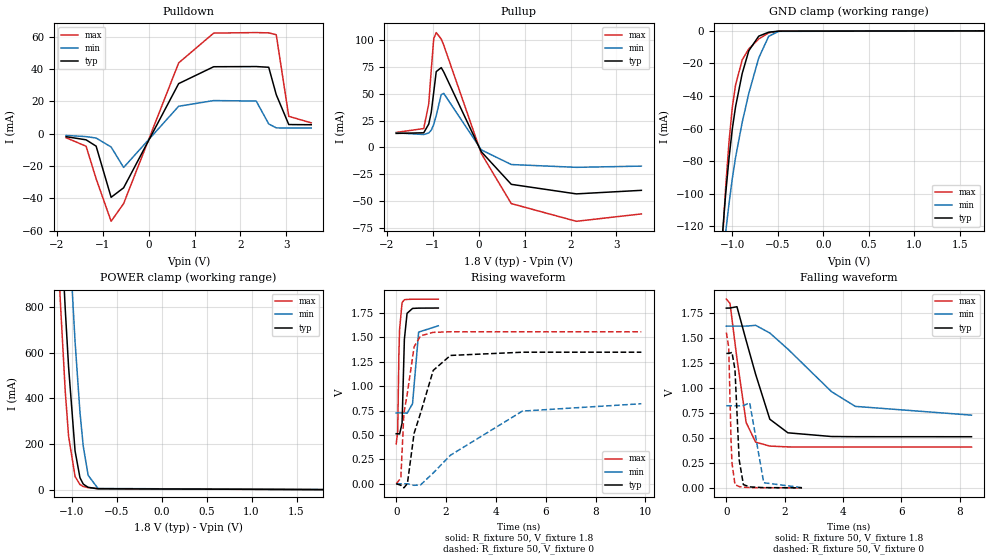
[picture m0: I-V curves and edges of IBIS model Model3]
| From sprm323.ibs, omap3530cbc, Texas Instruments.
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| Model based on original model for BQ0232CS_7LM
|   Sub model BQ0232CS_7LM_PU_ON_1P8
[model]   Model3
|[Input Load]   PU
|[Output Drive]
|Voltage   1.8V
|Mode   I/O
Model_type   I/O
Polarity   Non-Inverting
Enable   Active-Low
Vinl =  0.63
Vinh =  1.17
Cref =  15.0000pF
Rref =  100.0000M
Vref =  0V
Vmeas =  0.9
C_comp   0.8836195p   0.7578727p   1.042532p
[Model Spec]
Vinl   0.63   0.567   0.6615
Vinh   1.17   1.053   1.2285
[Temperature Range]   25   125   -40
[Voltage Range]   1.8   1.62   1.89
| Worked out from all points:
|   slope of the pulldown table from 0 to 0.27 V, typ, clamps not added: 18.2 ohm
|   slope of the pullup table from 0 to 0.27 V, typ, clamps not added: 15.1 ohm
|   GND clamp passes 1 mA (typ) near -0.61 V on its own axis
|   POWER clamp passes 1 mA (typ) near -0.57 V on its own axis
|   rising waveform, R_fixture 50, V_fixture 1.8: 20-80 % time 81.8ps typ, 143ps min, 65.1ps max; typ from 0.513 V to 1.8 V
|   rising waveform, R_fixture 50, V_fixture 0: 20-80 % time 778ps typ, 2.51ns min, 382ps max; typ from 0.001 V to 1.35 V
|   falling waveform, R_fixture 50, V_fixture 1.8: 20-80 % time 759ps typ, 1.98ns min, 424ps max; typ from 1.8 V to 0.513 V
|   falling waveform, R_fixture 50, V_fixture 0: 20-80 % time 127ps typ, 250ps min, 81.8ps max; typ from 1.35 V to 0.002 V
[POWER_clamp]
-1.8V     7.03A      7.477A     6.772A
-1.182V   1.672A     2.34A      1.267A
-1.164V   1.518A     2.189A     1.114A
-1.127V   1.216A     1.889A     820.5mA
-1.073V   791.2mA    1.448A     431.2mA
-1.036V   538.2mA    1.164A     234.6mA
-963.6mV  169mA      647.7mA    57.33mA
-909.1mV  52.04mA    338.7mA    22.18mA
-872.7mV  24.24mA    189.9mA    13.42mA
-818.2mV  9.922mA    62.63mA    8.566mA
-709.1mV  3.895mA    5.035mA    3.813mA
1.8V      4.518nA    3.065nA    7.561nA
[Pulldown]
-1.8V     -1.896mA   -1.14mA    -2.549mA
-1.364V   -3.858mA   -1.868mA   -7.811mA
-1.145V   -7.758mA   -2.749mA   -27.9mA
-818.2mV  -39.37mA   -8.281mA   -54.21mA
-545.5mV  -33.5mA    -20.95mA   -43.25mA
654.5mV   30.89mA    16.9mA     43.69mA
1.418V    41.32mA    20.41mA    62.11mA
2.345V    41.43mA    20.12mA    62.44mA
2.618V    40.99mA    5.968mA    62.24mA
2.782V    24.07mA    3.525mA    61.09mA
3.055V    5.586mA    3.449mA    10.68mA
3.545V    5.467mA    3.446mA    6.63mA
[Pullup]
-1.8V     13mA       13.47mA    13.94mA
-1.2V     13.58mA    11.97mA    17.52mA
-1.091V   21.69mA    13.4mA     40.45mA
-1.036V   32.56mA    16.02mA    72.07mA
-981.8mV  51.55mA    21.35mA    101.5mA
-927.3mV  70.65mA    29.73mA    107.1mA
-818.2mV  74.4mA     49.19mA    101mA
-763.6mV  70.3mA     50.34mA    95.36mA
54.55mV   -4.056mA   -2.362mA   -5.695mA
709.1mV   -34.52mA   -16.04mA   -52.48mA
2.127V    -43.43mA   -18.65mA   -69.01mA
3.545V    -40.12mA   -17.52mA   -62.13mA
[GND_clamp]
-1.8V     -750.7mA   -623.3mA   -941.3mA
-1.109V   -125.7mA   -143.5mA   -129.9mA
-1.073V   -100.4mA   -123.9mA   -96.49mA
-1.036V   -78.3mA    -106.2mA   -68.25mA
-1V       -60.36mA   -90.76mA   -47.12mA
-963.6mV  -46.51mA   -77.61mA   -33.16mA
-890.9mV  -26.17mA   -56.18mA   -17.83mA
-818.2mV  -12.21mA   -38.34mA   -11.05mA
-709.1mV  -3.258mA   -16.63mA   -4.995mA
-600mV    -827uA     -3.39mA    -1.226mA
-490.9mV  -188.5uA   -312.9uA   -225.1uA
1.764V    -5.55uA    13.97uA    -26.17uA
[Ramp]
dV/dt_f  0.7828072/0.7676471n  0.5423856/2.017313n   0.9050072/0.4292582n
dV/dt_r  0.8329624/0.7786561n  0.5086068/2.534443n   0.9650069/0.3827876n
R_load = 50
[Rising Waveform]
R_fixture = 50
V_fixture = 1.8
V_fixture_min = 1.62
V_fixture_max = 1.89
0s        513.1mV    725.9mV    409.6mV
60ps      512.9mV    726mV      534.4mV
108ps     511.6mV    726.1mV    1.328V
136ps     510.3mV    726.2mV    1.583V
236ps     620.7mV    726.2mV    1.854V
328ps     1.479V     725.4mV    1.884V
436ps     1.745V     722.6mV    1.887V
656ps     1.795V     820.5mV    1.889V
900ps     1.798V     1.553V     1.889V
1.69ns    1.799V     1.617V     1.89V
[Rising Waveform]
R_fixture = 50
V_fixture = 0
V_fixture_min = 0
V_fixture_max = 0
0s        1.242mV    788.6uV    1.474mV
186ps     -13.72mV   801.3uV    58.83mV
308ps     -40.65mV   964.4uV    720.1mV
450ps     4.147mV    769.5uV    931.8mV
718ps     517.2mV    -14.65mV   1.402V
978ps     725.1mV    -9.96mV    1.515V
1.486ns   1.161V     111.5mV    1.55V
2.176ns   1.314V     293mV      1.556V
5.066ns   1.347V     744.7mV    1.556V
9.84ns    1.347V     819.9mV    1.556V
[Falling Waveform]
R_fixture = 50
V_fixture = 1.8
V_fixture_min = 1.62
V_fixture_max = 1.89
0s        1.8V       1.62V      1.89V
126ps     1.801V     1.62V      1.847V
364ps     1.814V     1.62V      1.295V
680ps     1.475V     1.62V      654.8mV
1.004ns   1.138V     1.628V     458.9mV
1.49ns    688.4mV    1.551V     419.6mV
2.11ns    552.3mV    1.39V      411.3mV
3.6ns     515.4mV    965.2mV    409.7mV
4.418ns   513.6mV    816.9mV    409.6mV
8.402ns   513.1mV    729.2mV    409.6mV
[Falling Waveform]
R_fixture = 50
V_fixture = 0
V_fixture_min = 0
V_fixture_max = 0
0s        1.347V     823.1mV    1.556V
82ps      1.347V     823.2mV    1.407V
162ps     1.353V     822.8mV    475.2mV
192ps     1.359V     822.6mV    253.9mV
296ps     1.186V     822.2mV    34.87mV
440ps     283.5mV    821.9mV    14.12mV
584ps     34.06mV    825.6mV    8.321mV
802ps     10.99mV    852.1mV    3.972mV
1.282ns   4.015mV    52.57mV    2.35mV
2.594ns   1.778mV    4.036mV    1.523mV
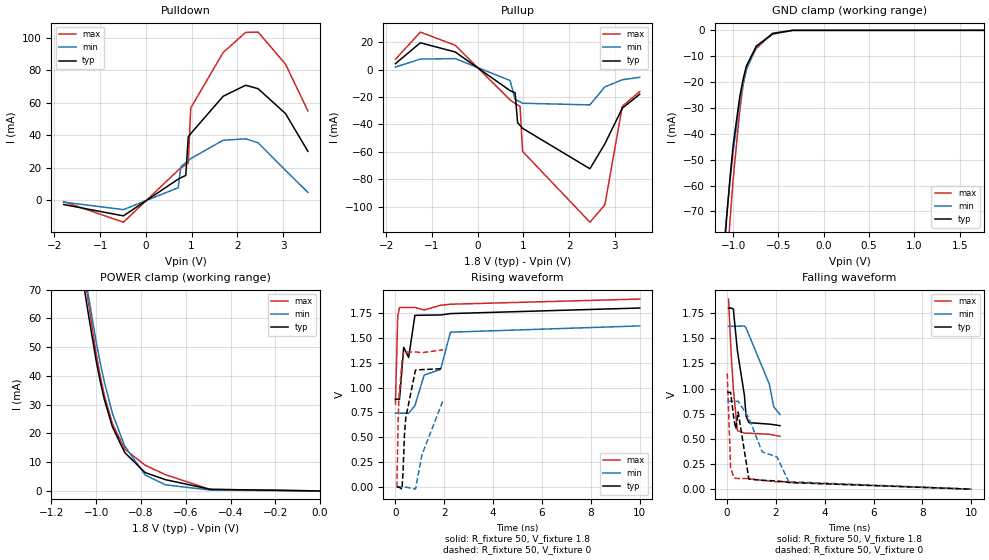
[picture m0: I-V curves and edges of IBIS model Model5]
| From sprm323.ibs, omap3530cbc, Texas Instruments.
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| Model based on original model for BQ0267CS_7LM
|   Sub model BQ0267CS_7LM_DS0_1
[model]   Model5
|[Input Load]
|[Output Drive] FAST
|Voltage   1.8V
|Mode   I/O
Model_type   I/O
Polarity   Non-Inverting
Enable   Active-Low
Vinl =  0.6615
Vinh =  1.2285
Cref =  15.0000pF
Rref =  100.0000M
Vref =  0V
Vmeas =  0.9
C_comp   1.666797p   1.351222p   1.845128p
[Model Spec]
Vinl   0.6615   0.6615   0.6615
Vinh   1.2285   1.2285   1.2285
[Temperature Range]   25   125   -40
[Voltage Range]   1.8   1.62   1.89
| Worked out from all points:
|   slope of the pulldown table from 0 to 0.27 V, typ, clamps not added: 50.1 ohm
|   slope of the pullup table from 0 to 0.27 V, typ, clamps not added: 40.2 ohm
|   GND clamp passes 1 mA (typ) near -0.54 V on its own axis
|   POWER clamp passes 1 mA (typ) near -0.53 V on its own axis
|   rising waveform, R_fixture 50, V_fixture 1.8: 20-80 % time 411ps typ, 1.15ns min, 49.5ps max; typ from 0.883 V to 1.8 V
|   rising waveform, R_fixture 50, V_fixture 0: 20-80 % time 242ps typ, 733ps min, 120ps max; typ from 0 V to 1.19 V
|   falling waveform, R_fixture 50, V_fixture 1.8: 20-80 % time 376ps typ, 836ps min, 231ps max; typ from 1.8 V to 0.631 V
|   falling waveform, R_fixture 50, V_fixture 0: 20-80 % time 363ps typ, 1.39ns min, 87.4ps max; typ from 0.963 V to 0 V
[POWER_clamp]
-1.8V     586.6mA    600.4mA    641.5mA
-1.055V   71.31mA    77.72mA    76.65mA
-1.036V   62.02mA    68.51mA    66.23mA
-1V       45.25mA    51.81mA    47.6mA
-981.8mV  38.06mA    44.48mA    39.84mA
-963.6mV  31.78mA    37.88mA    33.26mA
-927.3mV  22.24mA    26.91mA    23.34mA
-872.7mV  13.36mA    15.61mA    14.55mA
-781.8mV  6.402mA    5.553mA    8.957mA
-690.9mV  3.917mA    2.129mA    5.654mA
-490.9mV  560.2uA    303.2uA    525.6uA
0V        1.021nA    6.85nA     484.5pA
[Pulldown]
-1.8V     -2.794mA   -1.321mA   -1.013mA
-490.9mV  -9.78mA    -5.926mA   -13.68mA
709.1mV   12.91mA    7.574mA    18.43mA
763.6mV   13.7mA     20.47mA    19.62mA
872.7mV   15.15mA    23.06mA    21.83mA
927.3mV   38.86mA    24.31mA    22.83mA
981.8mV   40.94mA    25.53mA    56.76mA
1.691V    63.95mA    36.85mA    90.93mA
2.182V    70.72mA    37.7mA     103.3mA
2.455V    68.62mA    35.28mA    103.5mA
3.055V    53.27mA    18.28mA    83.74mA
3.545V    30mA       4.691mA    54.91mA
[Pullup]
-1.8V     4.285mA    1.799mA    7.469mA
-1.255V   19.54mA    7.627mA    27.35mA
-490.9mV  12.81mA    7.987mA    17.71mA
709.1mV   -15.4mA    -8.007mA   -22.19mA
818.2mV   -16.98mA   -21.6mA    -24.72mA
872.7mV   -38.66mA   -22.67mA   -25.85mA
927.3mV   -40.79mA   -23.66mA   -26.89mA
981.8mV   -42.88mA   -24.58mA   -59.72mA
2.455V    -72.41mA   -25.78mA   -111.4mA
2.782V    -54.23mA   -12.68mA   -98.79mA
3.164V    -28.18mA   -7.43mA    -26.77mA
3.545V    -18.02mA   -5.657mA   -16.05mA
[GND_clamp]
-1.8V     -511.9mA   -404mA     -763.6mA
-1.109V   -90.66mA   -85.99mA   -119mA
-1.073V   -73.05mA   -71.96mA   -94.34mA
-1.036V   -57.45mA   -58.82mA   -74.12mA
-1V       -44.37mA   -46.83mA   -57.58mA
-927.3mV  -25.68mA   -27.61mA   -31.09mA
-890.9mV  -18.99mA   -20.64mA   -21.3mA
-854.5mV  -13.83mA   -15.29mA   -14.76mA
-745.5mV  -6.156mA   -6.246mA   -7.023mA
-563.6mV  -1.279mA   -1.488mA   -1.068mA
-345.5mV  -12uA      -40.39uA   -6.042uA
1.764V    914.5pA    178nA      451pA
[Ramp]
dV/dt_f 0.73095974/0.38379942n 0.55947708/0.85717248n 0.83404804/0.23511458n
dV/dt_r 0.75622532/0.26487678n 0.57083634/0.77084163n  0.8583294/0.12546927n
R_load = 50
[Rising Waveform]
R_fixture = 50
V_fixture = 1.8
V_fixture_min = 1.62
V_fixture_max = 1.89
0s        883.3mV    742.6mV    834.2mV
94ps      883.6mV    742.6mV    1.719V
167.3ps   882.9mV    742.6mV    1.804V
339.2ps   1.405V     742.6mV    1.806V
541.7ps   1.303V     742.4mV    1.806V
797.2ps   1.726V     818.8mV    1.806V
1.176ns   1.728V     1.126V     1.78V
1.849ns   1.73V      1.183V     1.828V
2.253ns   1.744V     1.557V     1.838V
10ns      1.8V       1.62V      1.89V
[Rising Waveform]
R_fixture = 50
V_fixture = 0
V_fixture_min = 0
V_fixture_max = 0
60.42ps   412.6nV    320.8nV    639.1nV
109.2ps   529.4uV    -575.8nV   637.6mV
137.7ps   847.9uV    -190.9nV   872.8mV
268.8ps   -20.92mV   -1.371uV   1.264V
310.7ps   143.9mV    -5.839uV   1.34V
369ps     522.1mV    -23.57uV   1.355V
420.7ps   692.8mV    -32.43uV   1.357V
819.9ps   1.176V     -19.44mV   1.358V
1.089ns   1.181V     326.9mV    1.351V
1.954ns   1.19V      874.1mV    1.38V
[Falling Waveform]
R_fixture = 50
V_fixture = 1.8
V_fixture_min = 1.62
V_fixture_max = 1.89
65.25ps   1.8V       1.62V      1.89V
163.3ps   1.802V     1.62V      1.375V
260.9ps   1.791V     1.62V      999.2mV
426.2ps   1.378V     1.62V      582.3mV
714.5ps   931.3mV    1.622V     557.3mV
781.9ps   726.5mV    1.603V     556.7mV
897.6ps   661.4mV    1.534V     556.2mV
1.734ns   646.5mV    1.044V     545.9mV
1.914ns   641.1mV    818.6mV    537.8mV
2.171ns   631.3mV    742.6mV    525.5mV
[Falling Waveform]
R_fixture = 50
V_fixture = 0
V_fixture_min = 0
V_fixture_max = 0
11.29ps   962.6mV    874.1mV    1.15V
149.4ps   962.1mV    874.2mV    214.5mV
287.4ps   691.7mV    874.1mV    113mV
359.8ps   599.2mV    874mV      108.6mV
459ps     766.6mV    874.3mV    106.1mV
897.4ps   99.46mV    707.1mV    104.7mV
1.441ns   88.36mV    370.3mV    87.7mV
2.051ns   81.81mV    320.1mV    72.31mV
2.541ns   66.34mV    66.55mV    74.2mV
10.01ns   412.6nV    320.8nV    639.1nV
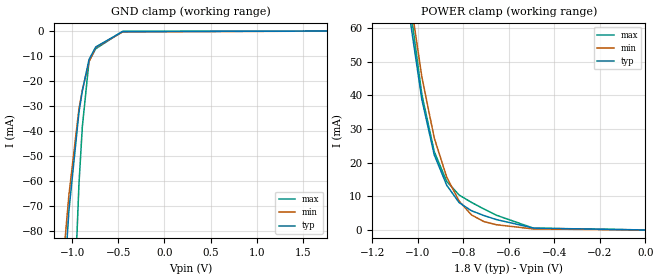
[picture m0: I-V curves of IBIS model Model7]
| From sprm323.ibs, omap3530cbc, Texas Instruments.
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| Model based on original model for BQ0267CS_7LM
|   Sub model Q0267CS_7LM_PUPD_OFF_1P8
[model]   Model7
|[Input Load]   PI
|[Output Drive]
|Voltage   1.8V
|Mode   INPUT
Model_type   Input
Polarity   Non-Inverting
Vinl =  0.6615
Vinh =  1.2285
C_comp   1.666797p   1.351222p   1.845128p
[Model Spec]
Vinl   0.6615   0.6615   0.6615
Vinh   1.2285   1.2285   1.2285
[Temperature Range]   25   125   -40
[Voltage Range]   1.8   1.62   1.89
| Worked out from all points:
|   GND clamp passes 1 mA (typ) near -0.54 V on its own axis
|   POWER clamp passes 1 mA (typ) near -0.53 V on its own axis
[POWER_clamp]
-1.8V     610mA      624.3mA    666.8mA
-1.055V   73.82mA    80.42mA    79.1mA
-1.036V   63.64mA    70.35mA    67.73mA
-981.8mV  38.72mA    45.44mA    40.24mA
-927.3mV  22.3mA     27.3mA     23.26mA
-872.7mV  13.29mA    15.71mA    14.41mA
-818.2mV  8.141mA    8.587mA    10.39mA
-763.6mV  5.702mA    4.45mA     8.176mA
-709.1mV  4.278mA    2.488mA    6.219mA
-654.5mV  3.09mA     1.556mA    4.377mA
-490.9mV  550.4uA    298.8uA    514.7uA
0V        1.017nA    6.506nA    484.9pA
[GND_clamp]
-1.8V     -588mA     -437.3mA   -1.301A
-1.291V   -227.1mA   -178.9mA   -507.6mA
-1.255V   -202.5mA   -161.3mA   -452.9mA
-1.218V   -178.6mA   -144.2mA   -399.5mA
-1.182V   -155.1mA   -127.4mA   -347.1mA
-1.036V   -71.82mA   -65.54mA   -162.6mA
-927.3mV  -32.49mA   -31.17mA   -61.3mA
-890.9mV  -24.01mA   -23.69mA   -38.38mA
-818.2mV  -11.4mA    -12.27mA   -12.07mA
-745.5mV  -6.359mA   -6.545mA   -7.07mA
-454.5mV  -197.5uA   -355.8uA   -112.4uA
1.764V    930.5pA    221nA      451.4pA
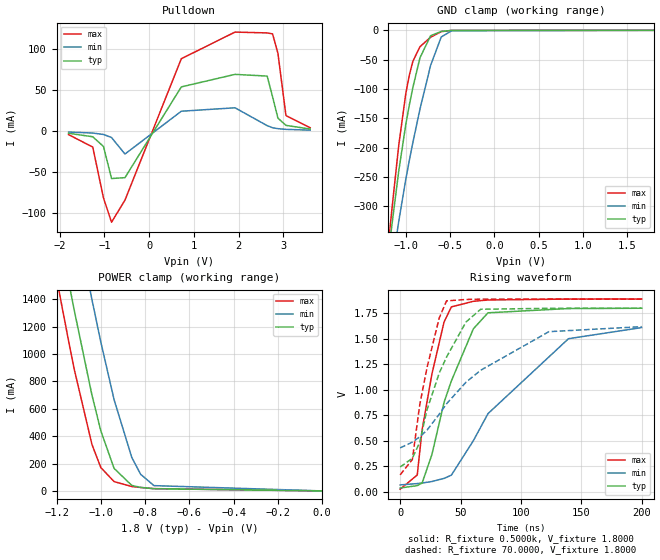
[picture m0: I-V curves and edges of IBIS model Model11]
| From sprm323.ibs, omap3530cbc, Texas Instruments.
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| Model based on original model for BQ0246S_7LM
|   Sub model BQ0246S_7LM_FA_ST
[model]   Model11
|[Input Load]
|[Output Drive] STANDARD
|Voltage   1.8000V
|Mode   I/O_OPEN_DRAIN
Model_type   I/O_open_drain
Polarity   Non-Inverting
Enable   Active-Low
Vinl =   0.6615V
Vinh =   1.0530V
Vmeas =   0.9000V
Cref =  15.0000pF
Rref =  70.0000
Vref =  1.8V
C_comp   27.0699pF   15.4565pF   39.2456pF
[Temperature Range]   25.0000   0.1250k   -40.0000
[Voltage Range]   1.8000V   1.6200V   1.8900V
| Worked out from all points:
|   slope of the pulldown table from 0 to 0.27 V, typ, clamps not added: 11.1 ohm
|   GND clamp passes 1 mA (typ) near -0.56 V on its own axis
|   POWER clamp passes 1 mA (typ) near -0.50 V on its own axis
|   rising waveform, R_fixture 0.5000k, V_fixture 1.8000: 20-80 % time 27.8ns typ, 59ns min, 16.5ns max; typ from 0.036 V to 1.8 V
|   rising waveform, R_fixture 70.0000, V_fixture 1.8000: 20-80 % time 28ns typ, 63ns min, 16.1ns max; typ from 0.241 V to 1.8 V
[Pulldown]
-1.8V     -2.861mA   -1.365mA   -4.522mA
-1.26V    -7.077mA   -2.577mA   -19.59mA
-1.02V    -18.91mA   -4.3mA     -81.42mA
-840mV    -57.79mA   -7.999mA   -110.8mA
-540mV    -56.73mA   -28.06mA   -84.07mA
720mV     53.46mA    23.92mA    87.65mA
1.92V     68.66mA    28.11mA    120mA
2.64V     66.58mA    6.388mA    119mA
2.76V     41.61mA    3.901mA    117.8mA
2.88V     15.59mA    2.748mA    94.37mA
3.06V     6.726mA    1.88mA     18.65mA
3.6V      2.318mA    948uA      3.884mA
[GND_clamp]
-1.8V     -1.221A    -1.151A    -1.363A
-1.2V     -386.5mA   -449.7mA   -370.2mA
-1.16V    -335.5mA   -406.8mA   -309.4mA
-1.08V    -240.2mA   -325.8mA   -196.3mA
-1V       -160.3mA   -253.8mA   -107.7mA
-960mV    -127.1mA   -221.5mA   -76.33mA
-920mV    -97.28mA   -191.1mA   -52.71mA
-840mV    -46.78mA   -134.3mA   -27.94mA
-720mV    -9.253mA   -59.82mA   -11.79mA
-600mV    -1.888mA   -11.35mA   -2.27mA
-480mV    -137.6uA   -650.4uA   -84.11uA
1.8V      510.5nA    3.198uA    487.6nA
[POWER_clamp]
-1.8V     7.644A     8.363A     7.23A
-1.2V     2.004A     2.755A     1.56A
-1.18V    1.829A     2.578A     1.386A
-1.14V    1.486A     2.23A      1.05A
-1.12V    1.32A      2.059A     889mA
-1.04V    700.2mA    1.398A     339.6mA
-1V       439.3mA    1.088A     170.8mA
-940mV    164.6mA    666.7mA    68.12mA
-860mV    40.26mA    244.2mA    32.16mA
-820mV    25.74mA    121.5mA    25.05mA
-760mV    16.31mA    38.76mA    16.75mA
0V        510.5nA    462.5nA    537.3nA
[Ramp]
dV/dt_r   0.1360m/25.9658n   0.3869m/25.8402n   0.1700m/14.4286n
dV/dt_f   0.2433/53.9460n   6.1184m/16.5953n   0.7167/79.2824n
R_load = 0.5000k
[Rising Waveform]
R_fixture = 0.5000k
V_fixture = 1.8000
V_fixture_min = 1.6200
V_fixture_max = 1.8900
0s        35.54mV    65.74mV    23.91mV
14.14ns   58.51mV    78.58mV    163mV
18.18ns   84.16mV    84.16mV    607mV
26.26ns   362.3mV    98.9mV     1.153V
36.36ns   876.8mV    129.6mV    1.665V
42.42ns   1.087V     161.7mV    1.813V
60.61ns   1.598V     499.7mV    1.868V
72.73ns   1.755V     765.4mV    1.881V
139.4ns   1.797V     1.501V     1.89V
200ns     1.8V       1.61V      1.89V
[Rising Waveform]
R_fixture = 70.0000
V_fixture = 1.8000
V_fixture_min = 1.6200
V_fixture_max = 1.8900
0s        241.4mV    429.3mV    164.4mV
10.1ns    327mV      485.8mV    315.1mV
16.16ns   482.7mV    537mV      848.5mV
22.22ns   801.9mV    603.4mV    1.216V
32.32ns   1.163V     758.9mV    1.703V
38.38ns   1.32V      861.7mV    1.872V
54.55ns   1.665V     1.074V     1.886V
66.67ns   1.79V      1.191V     1.889V
123.2ns   1.799V     1.57V      1.89V
200ns     1.8V       1.619V     1.89V
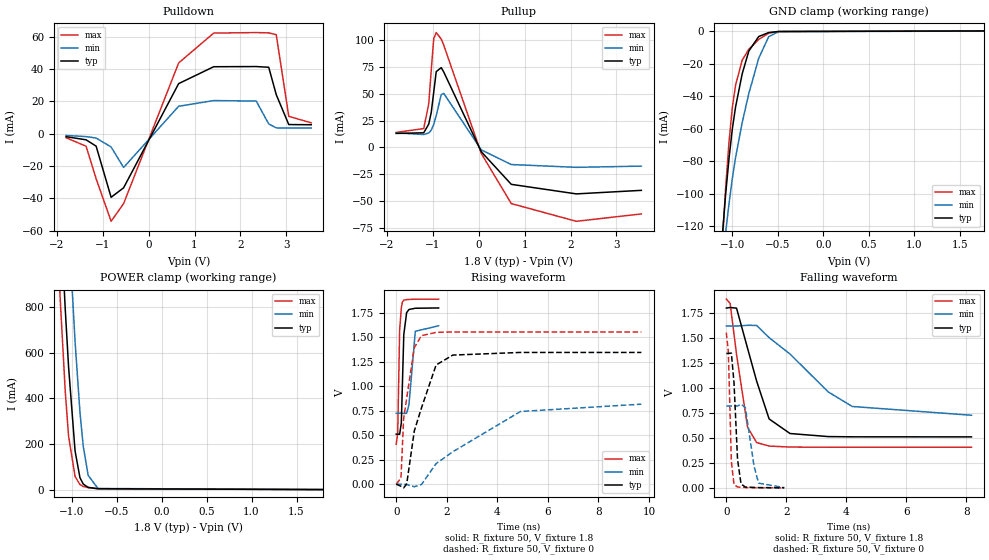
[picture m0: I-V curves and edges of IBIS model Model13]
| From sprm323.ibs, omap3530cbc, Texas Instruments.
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| Model based on original model for BQ0253CS_7LM
|   Sub model BQ0253CS_7LM_PD_ON_1P8
[model]   Model13
|[Input Load]   PD
|[Output Drive]
|Voltage   1.8V
|Mode   I/O
Model_type   I/O
Polarity   Non-Inverting
Enable   Active-Low
Vinl =  0.63
Vinh =  1.17
Cref =  15.0000pF
Rref =  100.0000M
Vref =  0V
Vmeas =  0.9
C_comp   0.8825327p   0.7587673p   1.039339p
[Model Spec]
Vinl   0.63   0.567   0.6615
Vinh   1.17   1.053   1.2285
[Temperature Range]   25   125   -40
[Voltage Range]   1.8   1.62   1.89
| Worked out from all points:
|   slope of the pulldown table from 0 to 0.27 V, typ, clamps not added: 18.2 ohm
|   slope of the pullup table from 0 to 0.27 V, typ, clamps not added: 15.1 ohm
|   GND clamp passes 1 mA (typ) near -0.61 V on its own axis
|   POWER clamp passes 1 mA (typ) near -0.56 V on its own axis
|   rising waveform, R_fixture 50, V_fixture 1.8: 20-80 % time 81.7ps typ, 139ps min, 65.7ps max; typ from 0.51 V to 1.8 V
|   rising waveform, R_fixture 50, V_fixture 0: 20-80 % time 782ps typ, 2.51ns min, 384ps max; typ from 0 V to 1.34 V
|   falling waveform, R_fixture 50, V_fixture 1.8: 20-80 % time 756ps typ, 1.98ns min, 422ps max; typ from 1.8 V to 0.51 V
|   falling waveform, R_fixture 50, V_fixture 0: 20-80 % time 126ps typ, 247ps min, 80.1ps max; typ from 1.34 V to 0.001 V
[POWER_clamp]
-1.8V     7.03A      7.477A     6.772A
-1.182V   1.672A     2.34A      1.267A
-1.164V   1.518A     2.189A     1.114A
-1.127V   1.216A     1.889A     820.5mA
-1.073V   791.2mA    1.448A     431.2mA
-1.036V   538.2mA    1.164A     234.6mA
-963.6mV  169mA      647.7mA    57.37mA
-909.1mV  52.03mA    338.6mA    22.22mA
-872.7mV  24.23mA    189.8mA    13.46mA
-818.2mV  9.921mA    62.61mA    8.619mA
-709.1mV  3.907mA    5.01mA     3.883mA
1.8V      125.3uA    51.98uA    219uA
[Pulldown]
-1.8V     -1.896mA   -1.14mA    -2.549mA
-1.364V   -3.858mA   -1.868mA   -7.811mA
-1.145V   -7.758mA   -2.749mA   -27.9mA
-818.2mV  -39.37mA   -8.281mA   -54.21mA
-545.5mV  -33.49mA   -20.95mA   -43.25mA
654.5mV   30.89mA    16.9mA     43.68mA
1.418V    41.32mA    20.41mA    62.11mA
2.345V    41.43mA    20.12mA    62.44mA
2.618V    40.99mA    5.968mA    62.24mA
2.782V    24.07mA    3.525mA    61.09mA
3.055V    5.586mA    3.449mA    10.68mA
3.545V    5.467mA    3.446mA    6.63mA
[Pullup]
-1.8V     13mA       13.47mA    13.94mA
-1.2V     13.58mA    11.97mA    17.52mA
-1.091V   21.69mA    13.4mA     40.45mA
-1.036V   32.56mA    16.02mA    72.07mA
-981.8mV  51.55mA    21.35mA    101.5mA
-927.3mV  70.65mA    29.73mA    107.1mA
-818.2mV  74.4mA     49.19mA    101mA
-763.6mV  70.3mA     50.34mA    95.36mA
54.55mV   -4.057mA   -2.362mA   -5.698mA
709.1mV   -34.52mA   -16.04mA   -52.48mA
2.127V    -43.43mA   -18.65mA   -69mA
3.545V    -40.12mA   -17.52mA   -62.13mA
[GND_clamp]
-1.8V     -750.7mA   -623.3mA   -941.3mA
-1.109V   -125.7mA   -143.5mA   -129.9mA
-1.073V   -100.4mA   -123.9mA   -96.51mA
-1.036V   -78.32mA   -106.2mA   -68.27mA
-1V       -60.38mA   -90.77mA   -47.15mA
-963.6mV  -46.54mA   -77.63mA   -33.2mA
-890.9mV  -26.21mA   -56.2mA    -17.88mA
-818.2mV  -12.24mA   -38.36mA   -11.11mA
-709.1mV  -3.293mA   -16.65mA   -5.049mA
-600mV    -851.2uA   -3.412mA   -1.264mA
-490.9mV  -193.3uA   -326.3uA   -232.3uA
1.764V    125uA      52.52uA    217.2uA
[Ramp]
dV/dt_f  0.7816467/0.7626196n  0.5427005/2.008564n   0.9017885/0.4259703n
dV/dt_r  0.8334853/0.7831189n   0.507515/2.539683n   0.9661789/0.38481n
R_load = 50
[Rising Waveform]
R_fixture = 50
V_fixture = 1.8
V_fixture_min = 1.62
V_fixture_max = 1.89
0s        510.1mV    723.2mV    406.6mV
60ps      510.1mV    723.2mV    523.5mV
136ps     509.1mV    723.6mV    1.575V
202ps     623.1mV    723.8mV    1.798V
242ps     988.1mV    723.2mV    1.856V
300ps     1.526V     720.9mV    1.878V
412ps     1.75V      722.7mV    1.883V
504ps     1.782V     811mV      1.885V
756ps     1.795V     1.56V      1.887V
1.678ns   1.798V     1.616V     1.888V
[Rising Waveform]
R_fixture = 50
V_fixture = 0
V_fixture_min = 0
V_fixture_max = 0
0s        195.2nV    87.26nV    423.3nV
188ps     -21.53mV   150.1uV    61.95mV
294ps     -37.98mV   304.7uV    667.4mV
416ps     3.081mV    -4.953mV   878.6mV
716ps     543.1mV    -26.29mV   1.394V
998ps     776.9mV    -4.202mV   1.515V
1.578ns   1.216V     209.8mV    1.549V
2.238ns   1.317V     330.4mV    1.553V
4.912ns   1.344V     741.1mV    1.553V
9.696ns   1.344V     816.1mV    1.553V
[Falling Waveform]
R_fixture = 50
V_fixture = 1.8
V_fixture_min = 1.62
V_fixture_max = 1.89
0s        1.799V     1.619V     1.888V
126ps     1.804V     1.619V     1.846V
340ps     1.798V     1.619V     1.335V
708ps     1.396V     1.626V     606.8mV
1.01ns    1.068V     1.625V     453.3mV
1.426ns   689.6mV    1.503V     418.4mV
2.122ns   543.8mV    1.339V     408.2mV
3.4ns     513.1mV    959.3mV    406.7mV
4.198ns   510.8mV    814.2mV    406.6mV
8.172ns   510.1mV    726.5mV    406.6mV
[Falling Waveform]
R_fixture = 50
V_fixture = 0
V_fixture_min = 0
V_fixture_max = 0
0s        1.344V     819.4mV    1.553V
68ps      1.345V     819.3mV    1.358V
168ps     1.348V     818.5mV    259.5mV
256ps     1.051V     818mV      34mV
374ps     283.8mV    818.8mV    8.92mV
490ps     39.08mV    836.8mV    6.572mV
634ps     8.339mV    803.1mV    3.019mV
924ps     4.358mV    216.7mV    1.601mV
1.076ns   2.825mV    46.96mV    1.197mV
1.93ns    1.05mV     3.243mV    216.3uV
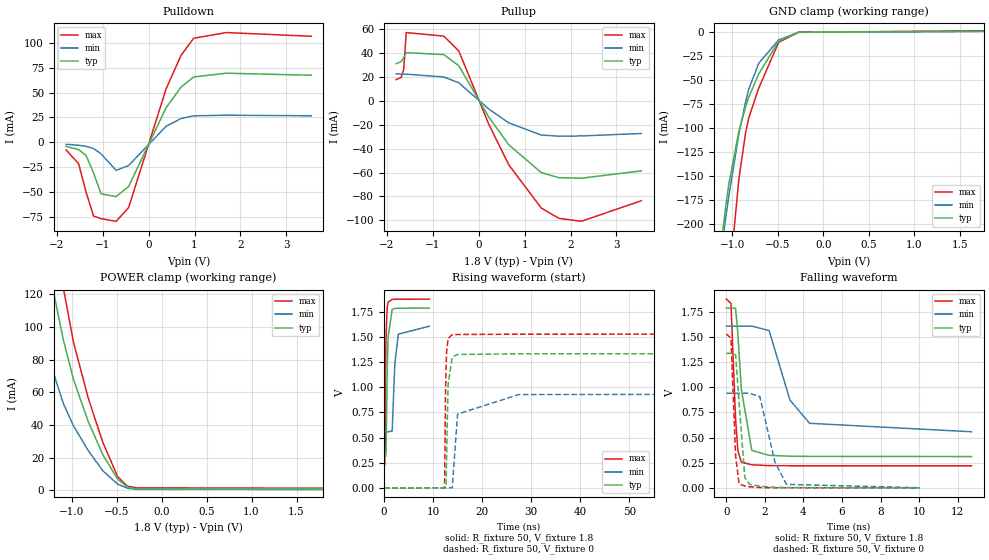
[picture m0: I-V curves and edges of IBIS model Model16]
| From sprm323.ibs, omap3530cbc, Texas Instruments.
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| Model based on original model for BQ0447S_7LM
|   Sub model BQ0447S_7LM_PD_1P8
[model]   Model16
|[Input Load]   PD
|[Output Drive]
|Voltage   1.8V
|Mode   I/O
Model_type   I/O
Polarity   Non-Inverting
Enable   Active-Low
Vinl =  0.63
Vinh =  1.17
Cref =  15.0000pF
Rref =  100.0000M
Vref =  0V
Vmeas =  0.9
C_comp   14.35822p   13.74686p   15.2046p
[Model Spec]
Vinl   0.63   0.567   0.6615
Vinh   1.17   1.053   1.2285
[Temperature Range]   25   125   -40
[Voltage Range]   1.8   1.62   1.89
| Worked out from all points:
|   slope of the pulldown table from 0 to 0.27 V, typ, clamps not added: 10.4 ohm
|   slope of the pullup table from 0 to 0.27 V, typ, clamps not added: 16.1 ohm
|   GND clamp passes 1 mA (typ) near -0.33 V on its own axis
|   POWER clamp passes 1 mA (typ) near -0.13 V on its own axis
|   rising waveform, R_fixture 50, V_fixture 1.8: 20-80 % time 307ps typ, 594ps min, 200ps max; typ from 0.311 V to 1.79 V
|   rising waveform, R_fixture 50, V_fixture 0: 20-80 % time 384ps typ, 1.88ns min, 237ps max; typ from 0 V to 1.34 V
|   falling waveform, R_fixture 50, V_fixture 1.8: 20-80 % time 392ps typ, 1.14ns min, 219ps max; typ from 1.79 V to 0.312 V
|   falling waveform, R_fixture 50, V_fixture 0: 20-80 % time 251ps typ, 649ps min, 167ps max; typ from 1.34 V to 0 V
[POWER_clamp]
-1.8V     305.1mA    204.4mA    383.6mA
-1.455V   195.4mA    123.8mA    251.7mA
-1.218V   125.5mA    74.32mA    166.4mA
-1.109V   96.07mA    55.6mA     128.9mA
-1.091V   91.4mA     52.78mA    122.8mA
-981.8mV  67.98mA    39.51mA    90.79mA
-818.2mV  42.27mA    24.48mA    56.62mA
-654.5mV  21.83mA    12.01mA    29.38mA
-490.9mV  6.932mA    3.908mA    8.522mA
-381.8mV  2.178mA    1.349mA    2.591mA
-272.7mV  1.138mA    691.5uA    1.615mA
1.8V      933.9uA    536.1uA    1.381mA
[Pulldown]
-1.8V     -4.045mA   -1.989mA   -7.643mA
-1.527V   -7.297mA   -2.932mA   -21.5mA
-1.364V   -13.13mA   -4.035mA   -50.14mA
-1.2V     -30.92mA   -6.241mA   -74.18mA
-1.036V   -51.82mA   -11.63mA   -76.78mA
-709.1mV  -54.59mA   -28.19mA   -79.4mA
-436.4mV  -44.39mA   -23.3mA    -65.67mA
381.8mV   34.97mA    16.22mA    53.98mA
709.1mV   55.69mA    23.96mA    87.69mA
981.8mV   65.76mA    26.68mA    104.7mA
1.691V    69.52mA    27.31mA    110.4mA
3.545V    67.5mA     26.69mA    106.7mA
[Pullup]
-1.8V     30.85mA    22.33mA    17.55mA
-1.691V   32.56mA    22.17mA    19.4mA
-1.636V   35.98mA    22.14mA    25.93mA
-1.582V   40.03mA    22.12mA    56.79mA
-763.6mV  38.43mA    19.71mA    53.83mA
-436.4mV  29.17mA    14.9mA     41.49mA
218.2mV   -13.72mA   -6.988mA   -19.72mA
654.5mV   -36.87mA   -18.56mA   -53.56mA
1.364V    -60.07mA   -28.75mA   -89.7mA
1.745V    -64.29mA   -29.65mA   -98.21mA
2.236V    -64.75mA   -29.49mA   -100.7mA
3.545V    -58.6mA    -27.43mA   -83.51mA
[GND_clamp]
-1.8V     -901.7mA   -764.8mA   -1.495A
-1.218V   -303.5mA   -297.4mA   -491.4mA
-1.182V   -270.4mA   -270.4mA   -440.2mA
-1.073V   -182mA     -193.6mA   -303.2mA
-1.036V   -157.1mA   -169.5mA   -261.2mA
-927.3mV  -103.1mA   -106.1mA   -152.8mA
-854.5mV  -78.21mA   -73.14mA   -105.2mA
-818.2mV  -67.54mA   -59.12mA   -89.17mA
-709.1mV  -43.63mA   -32.48mA   -58.38mA
-490.9mV  -9.712mA   -8.28mA    -10.82mA
-272.7mV  -274.8uA   -322.5uA   -285.7uA
1.764V    915.6uA    585.3uA    1.291mA
[Ramp]
dV/dt_f   0.887572/0.3876826n   0.632891/1.12856n   0.9965927/0.2174413n
dV/dt_r  0.8038869/0.3761196n  0.5648313/0.7944084n  0.9188858/0.2365951n
R_load = 50
[Rising Waveform]
R_fixture = 50
V_fixture = 1.8
V_fixture_min = 1.62
V_fixture_max = 1.89
0s        311.5mV    556.5mV    219.7mV
180ps     311.6mV    556.5mV    225mV
360ps     311.5mV    556.5mV    1.315V
420ps     323.9mV    556.5mV    1.49V
660ps     1.165V     556.6mV    1.794V
840ps     1.498V     556.9mV    1.848V
1.68ns    1.776V     566.4mV    1.876V
2.22ns    1.785V     1.238V     1.877V
2.94ns    1.787V     1.53V      1.877V
9.24ns    1.789V     1.608V     1.878V
[Rising Waveform]
R_fixture = 50
V_fixture = 0
V_fixture_min = 0
V_fixture_max = 0
0s        1.536uV    7.367uV    394.9nV
12.36ns   2.318uV    13.68uV    288.5uV
12.54ns   -202.3uV   2.345uV    917.6mV
12.66ns   6.815mV    336.2nV    1.207V
12.78ns   383.3mV    -339.6nV   1.355V
13.08ns   1.032V     -23.18nV   1.487V
13.92ns   1.302V     -463.7uV   1.524V
15ns      1.327V     733.5mV    1.526V
27.48ns   1.334V     928.3mV    1.529V
314.3ns   1.338V     939.7mV    1.531V
[Falling Waveform]
R_fixture = 50
V_fixture = 1.8
V_fixture_min = 1.62
V_fixture_max = 1.89
0s        1.789V     1.61V      1.878V
240ps     1.789V     1.61V      1.836V
480ps     1.786V     1.61V      685.4mV
600ps     1.531V     1.61V      369.4mV
780ps     979.6mV    1.61V      255.7mV
1.32ns    373.2mV    1.61V      229.8mV
2.22ns    323.9mV    1.565V     221.5mV
3.3ns     314.9mV    873.6mV    220.3mV
4.32ns    313.1mV    642.4mV    220.1mV
12.72ns   311.9mV    558.2mV    219.8mV
[Falling Waveform]
R_fixture = 50
V_fixture = 0
V_fixture_min = 0
V_fixture_max = 0
0s        1.339V     941.3mV    1.531V
240ps     1.339V     941.3mV    1.49V
480ps     1.325V     941.3mV    321.5mV
660ps     852.8mV    941.3mV    40.09mV
960ps     101.4mV    941.3mV    18.35mV
1.2ns     36.21mV    941.4mV    11.38mV
1.74ns    15.93mV    907.5mV    3.669mV
2.52ns    5.644mV    258.5mV    1.017mV
3.12ns    2.799mV    34.92mV    612.2uV
10.02ns   456.2uV    1.64mV     168.9uV
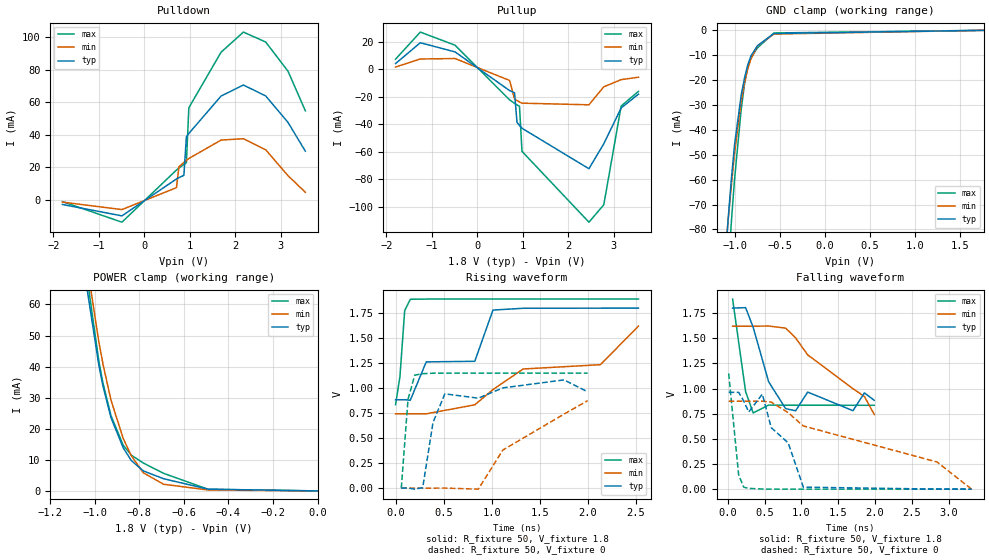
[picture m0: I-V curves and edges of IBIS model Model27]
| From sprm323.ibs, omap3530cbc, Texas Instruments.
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| Model based on original model for OQ0164CS_7LM
|   Sub model OQ0164CS_7LM_DS0_0
[model]   Model27
|[Input Load]
|[Output Drive] SLOW
|Voltage   1.8V
|Mode   3-STATE
Model_type   3-state
Polarity   Non-Inverting
Enable   Active-Low
Cref =  30.0000pF
Rref =  100.0000M
Vref =  0V
Vmeas =  0.9
C_comp   1.471p   1.219p   1.654p
[Temperature Range]   25   125   -40
[Voltage Range]   1.8   1.62   1.89
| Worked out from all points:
|   slope of the pulldown table from 0 to 0.27 V, typ, clamps not added: 50.1 ohm
|   slope of the pullup table from 0 to 0.27 V, typ, clamps not added: 40.2 ohm
|   GND clamp passes 1 mA (typ) near -0.54 V on its own axis
|   POWER clamp passes 1 mA (typ) near -0.53 V on its own axis
|   rising waveform, R_fixture 50, V_fixture 1.8: 20-80 % time 701ps typ, 1.43ns min, 46.5ps max; typ from 0.883 V to 1.8 V
|   rising waveform, R_fixture 50, V_fixture 0: 20-80 % time 109ps typ, 666ps min, 55.2ps max; typ from 0 V to 0.963 V
|   falling waveform, R_fixture 50, V_fixture 1.8: 20-80 % time 213ps typ, 888ps min, 114ps max; typ from 1.8 V to 0.883 V
|   falling waveform, R_fixture 50, V_fixture 0: 20-80 % time 388ps typ, 2.12ns min, 76.8ps max; typ from 0.963 V to 0 V
[POWER_clamp]
-1.8V     610.3mA    627.2mA    665.6mA
-1.055V   75.26mA    82.88mA    80.2mA
-1.036V   65.55mA    73.22mA    69.35mA
-981.8mV  40.41mA    47.92mA    41.72mA
-963.6mV  33.78mA    40.92mA    34.77mA
-927.3mV  23.58mA    29.2mA     24.2mA
-872.7mV  13.91mA    16.92mA    14.75mA
-836.4mV  9.787mA    11.36mA    11.53mA
-781.8mV  6.423mA    5.812mA    8.958mA
-690.9mV  3.917mA    2.14mA     5.654mA
-490.9mV  560.2uA    303.2uA    525.6uA
0V        1.021nA    6.85nA     484.6pA
[Pulldown]
-1.8V     -2.78mA    -1.318mA   -1.011mA
-490.9mV  -9.78mA    -5.926mA   -13.68mA
709.1mV   12.91mA    7.574mA    18.43mA
763.6mV   13.7mA     20.47mA    19.62mA
872.7mV   15.15mA    23.06mA    21.83mA
927.3mV   38.86mA    24.31mA    22.83mA
981.8mV   40.94mA    25.53mA    56.76mA
1.691V    63.95mA    36.85mA    90.93mA
2.182V    70.72mA    37.7mA     103.3mA
2.673V    64mA       30.87mA    97.18mA
3.164V    47.7mA     14.93mA    79.19mA
3.545V    30.01mA    4.712mA    54.87mA
[Pullup]
-1.8V     4.299mA    1.801mA    7.515mA
-1.255V   19.51mA    7.643mA    27.27mA
-490.9mV  12.81mA    7.987mA    17.71mA
709.1mV   -15.4mA    -8.007mA   -22.19mA
818.2mV   -16.98mA   -21.6mA    -24.72mA
872.7mV   -38.66mA   -22.67mA   -25.85mA
927.3mV   -40.79mA   -23.66mA   -26.89mA
981.8mV   -42.88mA   -24.58mA   -59.72mA
2.455V    -72.41mA   -25.77mA   -111.4mA
2.782V    -54.15mA   -12.65mA   -98.68mA
3.164V    -28.07mA   -7.41mA    -26.66mA
3.545V    -18mA      -5.643mA   -15.97mA
[GND_clamp]
-1.8V     -558.6mA   -442.4mA   -831mA
-1.109V   -96.01mA   -92.23mA   -125.3mA
-1.073V   -76.84mA   -76.85mA   -98.77mA
-1.036V   -59.94mA   -62.48mA   -77.23mA
-1V       -45.92mA   -49.41mA   -59.83mA
-927.3mV  -26.26mA   -28.64mA   -32.16mA
-890.9mV  -19.33mA   -21.23mA   -21.91mA
-854.5mV  -14.01mA   -15.6mA    -15.01mA
-818.2mV  -10.26mA   -11.4mA    -11.04mA
-745.5mV  -6.158mA   -6.269mA   -7.023mA
-563.6mV  -1.279mA   -1.488mA   -1.068mA
1.764V    914.5pA    178nA      451pA
[Ramp]
dV/dt_f 0.62267483/0.26488767n 0.55804971/0.91064802n 0.68511618/0.12588855n
dV/dt_r 0.67239606/0.16091045n  0.5716875/0.7881303n 0.70609335/55.937014p
R_load = 50
[Rising Waveform]
R_fixture = 50
V_fixture = 1.8
V_fixture_min = 1.62
V_fixture_max = 1.89
0s        883.3mV    742.6mV    834.2mV
45.72ps   883.3mV    742.6mV    1.115V
95.29ps   883.6mV    742.6mV    1.776V
153.4ps   879mV      742.6mV    1.888V
319.8ps   1.262V     742.6mV    1.89V
824.9ps   1.268V     832.9mV    1.89V
1.014ns   1.78V      984.9mV    1.89V
1.328ns   1.798V     1.191V     1.89V
2.133ns   1.799V     1.234V     1.89V
2.529ns   1.8V       1.62V      1.89V
[Rising Waveform]
R_fixture = 50
V_fixture = 0
V_fixture_min = 0
V_fixture_max = 0
59.76ps   412.6nV    320.8nV    639.1nV
129.6ps   1.117mV    -410.2nV   886.9mV
200ps     -9.977mV   312.7nV    1.13V
282.7ps   4.441mV    -2.522uV   1.144V
390.1ps   656.7mV    -32.05uV   1.149V
513.3ps   942.6mV    527.7uV    1.149V
861.2ps   899.1mV    -10.31mV   1.15V
1.117ns   1.002V     380.6mV    1.15V
1.754ns   1.082V     740.2mV    1.15V
2ns       962.6mV    874.1mV    1.15V
[Falling Waveform]
R_fixture = 50
V_fixture = 1.8
V_fixture_min = 1.62
V_fixture_max = 1.89
64.93ps   1.8V       1.62V      1.89V
241.2ps   1.805V     1.62V      970.6mV
343.9ps   1.61V      1.62V      758.1mV
554.2ps   1.068V     1.622V     836.1mV
785.5ps   800.7mV    1.601V     834.7mV
920.9ps   779.2mV    1.504V     834.5mV
1.085ns   965.3mV    1.335V     834.4mV
1.701ns   780.2mV    998.8mV    834.2mV
1.856ns   957mV      921.3mV    834.2mV
1.99ns    883.3mV    742.6mV    834.2mV
[Falling Waveform]
R_fixture = 50
V_fixture = 0
V_fixture_min = 0
V_fixture_max = 0
11.24ps   962.6mV    874.1mV    1.15V
146.7ps   962.7mV    874.2mV    142.1mV
215ps     878mV      874.2mV    20mV
283.6ps   767mV      874.1mV    7.87mV
468.9ps   944.9mV    874.4mV    1.203mV
589.2ps   611.9mV    865.5mV    380.2uV
820.6ps   459.6mV    760.4mV    32.75uV
1.026ns   20mV       628.5mV    -1.669uV
2.844ns   494.9uV    269.9mV    -1.861uV
3.313ns   412.6nV    320.8nV    639.1nV
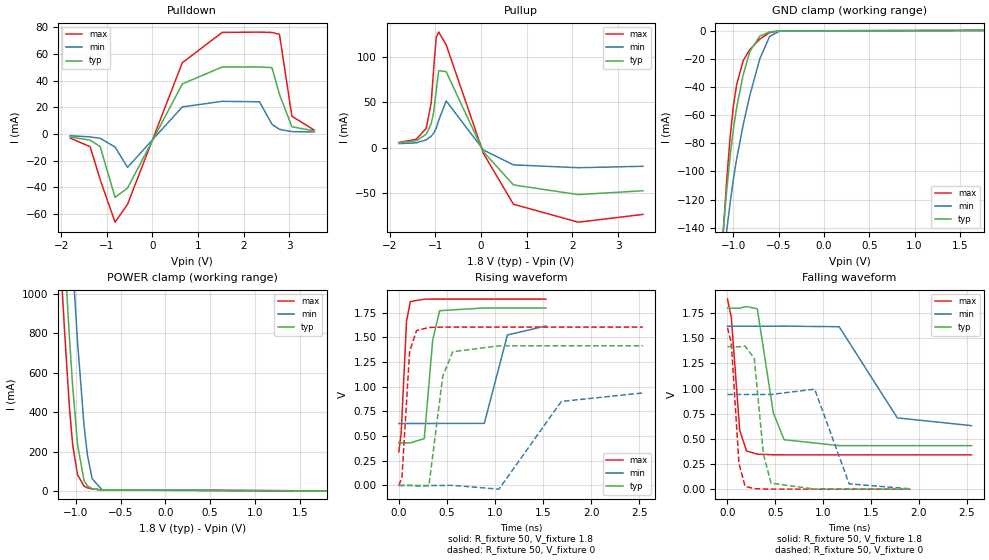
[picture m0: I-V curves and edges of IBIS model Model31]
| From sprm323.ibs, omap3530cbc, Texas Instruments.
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| Model based on original model for BQOMAPPROGIOCSHYFBPB_7LM
|   Sub model MODE00_PD_ON_1P8
[model]   Model31
|[Input Load]   PD
|[Output Drive] DS00
|Voltage   1.8V
|Mode   I/O
Model_type   I/O
Polarity   Non-Inverting
Enable   Active-Low
Vinl =  0.63
Vinh =  1.17
Cref =  15.0000pF
Rref =  100.0000M
Vref =  0V
Vmeas =  0.9
C_comp   0.8864943p   0.7714798p   1.034566p
[Model Spec]
Vinl   0.63   0.567   0.6615
Vinh   1.17   1.053   1.2285
[Temperature Range]   25   125   -40
[Voltage Range]   1.8   1.62   1.89
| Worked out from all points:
|   slope of the pulldown table from 0 to 0.27 V, typ, clamps not added: 15 ohm
|   slope of the pullup table from 0 to 0.27 V, typ, clamps not added: 12.7 ohm
|   GND clamp passes 1 mA (typ) near -0.60 V on its own axis
|   POWER clamp passes 1 mA (typ) near -0.55 V on its own axis
|   rising waveform, R_fixture 50, V_fixture 1.8: 20-80 % time 67.7ps typ, 114ps min, 44.7ps max; typ from 0.432 V to 1.8 V
|   rising waveform, R_fixture 50, V_fixture 0: 20-80 % time 114ps typ, 354ps min, 58.4ps max; typ from 0 V to 1.42 V
|   falling waveform, R_fixture 50, V_fixture 1.8: 20-80 % time 131ps typ, 343ps min, 70.2ps max; typ from 1.8 V to 0.432 V
|   falling waveform, R_fixture 50, V_fixture 0: 20-80 % time 89.6ps typ, 152ps min, 63.4ps max; typ from 1.42 V to 0 V
[POWER_clamp]
-1.8V     7.429A     8.065A     7.064A
-1.182V   1.663A     2.35A      1.259A
-1.164V   1.508A     2.193A     1.106A
-1.127V   1.206A     1.883A     813.3mA
-1.073V   782.1mA    1.435A     426.3mA
-1.036V   530.7mA    1.15A      232.5mA
-981.8mV  234.7mA    756.3mA    81.79mA
-909.1mV  52.86mA    331.4mA    24.54mA
-872.7mV  25.66mA    185.5mA    15.5mA
-818.2mV  11.27mA    62mA       10.15mA
-709.1mV  4.611mA    6.166mA    4.556mA
1.8V      101uA      43.59uA    177.4uA
[Pulldown]
-1.8V     -2.297mA   -1.36mA    -3.12mA
-1.364V   -4.671mA   -2.227mA   -9.575mA
-1.145V   -9.38mA    -3.274mA   -34.14mA
-818.2mV  -47.59mA   -9.8mA     -66.19mA
-545.5mV  -40.61mA   -25.06mA   -52.83mA
654.5mV   37.49mA    20.27mA    53.41mA
1.527V    50.21mA    24.47mA    76.15mA
2.345V    50.26mA    24.13mA    76.4mA
2.618V    49.72mA    7.252mA    76.1mA
2.782V    29.73mA    3.458mA    74.71mA
3.055V    5.351mA    1.737mA    13.28mA
3.545V    2.313mA    1.481mA    2.83mA
[Pullup]
-1.8V     5.219mA    4.328mA    5.561mA
-1.418V   7.442mA    5.119mA    9.078mA
-1.2V     14.66mA    8.527mA    21.18mA
-1.091V   26.28mA    12.48mA    49.44mA
-1.036V   39.59mA    15.94mA    87.85mA
-981.8mV  62.55mA    21.35mA    121.3mA
-927.3mV  84.62mA    29.89mA    127mA
-763.6mV  83.41mA    51.27mA    113mA
54.55mV   -4.817mA   -2.769mA   -6.752mA
709.1mV   -41.09mA   -19.06mA   -62.37mA
2.127V    -51.75mA   -22.2mA    -82.12mA
3.545V    -47.57mA   -20.61mA   -73.57mA
[GND_clamp]
-1.8V     -794.1mA   -670.5mA   -980.8mA
-1.109V   -139.6mA   -162.6mA   -140.1mA
-1.073V   -112.8mA   -141.5mA   -105.3mA
-1.036V   -89.25mA   -122.4mA   -75.78mA
-1V       -69.85mA   -105.6mA   -53.4mA
-963.6mV  -54.51mA   -90.99mA   -38.26mA
-890.9mV  -31.22mA   -66.62mA   -21.22mA
-818.2mV  -14.77mA   -45.88mA   -13.44mA
-709.1mV  -3.952mA   -20.19mA   -6.104mA
-600mV    -982.9uA   -4.198mA   -1.476mA
-490.9mV  -187.6uA   -374.7uA   -215.1uA
1.764V    101uA      43.71uA    177.3uA
[Ramp]
dV/dt_f  0.8474639/0.1305953n  0.6115163/0.3530971n   0.965386/72.47797p
dV/dt_r  0.8833712/0.1142406n  0.5889974/0.361005n   1.003082/59.16747p
R_load = 50
[Rising Waveform]
R_fixture = 50
V_fixture = 1.8
V_fixture_min = 1.62
V_fixture_max = 1.89
0s        432.4mV    627.8mV    341.1mV
24ps      432.7mV    627.8mV    529.5mV
80ps      432.8mV    627.8mV    1.665V
120ps     431.6mV    627.8mV    1.864V
264ps     475.1mV    627.8mV    1.888V
352ps     1.477V     628.2mV    1.889V
424ps     1.771V     628.6mV    1.889V
888ps     1.799V     628.9mV    1.889V
1.128ns   1.799V     1.525V     1.889V
1.528ns   1.799V     1.616V     1.889V
[Rising Waveform]
R_fixture = 50
V_fixture = 0
V_fixture_min = 0
V_fixture_max = 0
0s        199.9nV    132.8nV    426.1nV
32ps      337uV      2.324uV    81.59mV
112ps     1.812mV    3.194uV    1.36V
184ps     -7.564mV   71.77nV    1.571V
312ps     -4.267mV   -83.59uV   1.601V
456ps     1.106V     85.31uV    1.605V
560ps     1.355V     759.3uV    1.605V
1.04ns    1.415V     -37.62mV   1.605V
1.688ns   1.416V     851.2mV    1.605V
2.536ns   1.416V     937.8mV    1.605V
[Falling Waveform]
R_fixture = 50
V_fixture = 1.8
V_fixture_min = 1.62
V_fixture_max = 1.89
0s        1.799V     1.619V     1.889V
40ps      1.799V     1.619V     1.708V
128ps     1.799V     1.619V     585.4mV
200ps     1.815V     1.619V     379.3mV
312ps     1.792V     1.619V     347.4mV
480ps     756.2mV    1.619V     341.7mV
592ps     491.3mV    1.62V      341.2mV
1.168ns   432.6mV    1.614V     341.1mV
1.776ns   432.4mV    708mV      341.1mV
2.552ns   432.4mV    631.2mV    341.1mV
[Falling Waveform]
R_fixture = 50
V_fixture = 0
V_fixture_min = 0
V_fixture_max = 0
0s        1.416V     941.2mV    1.605V
40ps      1.416V     941.2mV    1.453V
120ps     1.415V     941.2mV    255.7mV
184ps     1.422V     941.2mV    27.27mV
280ps     1.301V     941.2mV    5.795mV
376ps     346.6mV    941.2mV    1.777mV
456ps     59.92mV    941.2mV    612.5uV
912ps     561.9uV    993.6mV    1.571uV
1.272ns   18.97uV    52.88mV    433.3nV
1.912ns   207nV      3.361mV    430.8nV
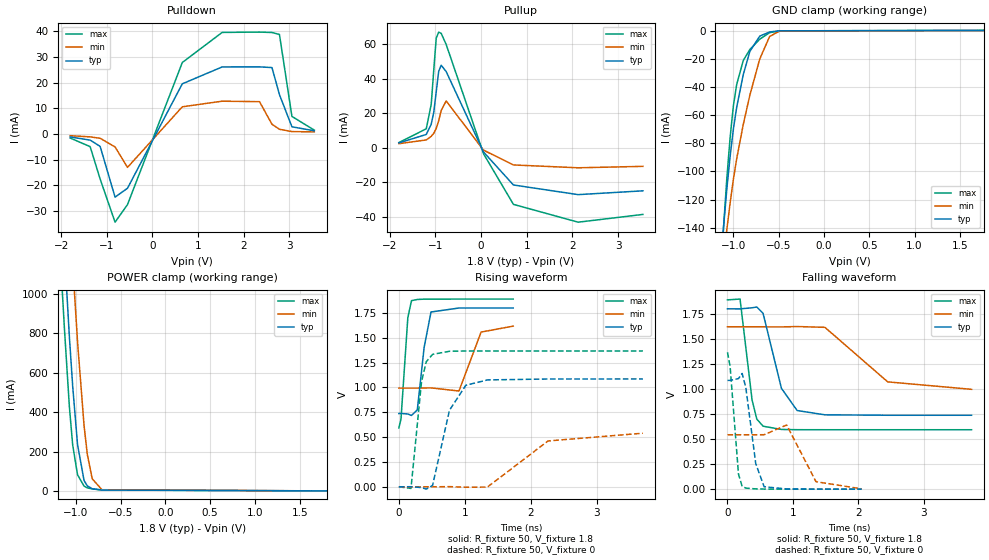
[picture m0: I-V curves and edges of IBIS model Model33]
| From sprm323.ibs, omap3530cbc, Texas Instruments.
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| Model based on original model for BQOMAPPROGIOCSHYFBPB_7LM
|   Sub model MODE10_PD_ON_1P8
[model]   Model33
|[Input Load]   PD
|[Output Drive] DS10
|Voltage   1.8V
|Mode   I/O
Model_type   I/O
Polarity   Non-Inverting
Enable   Active-Low
Vinl =  0.63
Vinh =  1.17
Cref =  15.0000pF
Rref =  100.0000M
Vref =  0V
Vmeas =  0.9
C_comp   0.8864943p   0.7714798p   1.034566p
[Model Spec]
Vinl   0.63   0.567   0.6615
Vinh   1.17   1.053   1.2285
[Temperature Range]   25   125   -40
[Voltage Range]   1.8   1.62   1.89
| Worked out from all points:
|   slope of the pulldown table from 0 to 0.27 V, typ, clamps not added: 28.9 ohm
|   slope of the pullup table from 0 to 0.27 V, typ, clamps not added: 24 ohm
|   GND clamp passes 1 mA (typ) near -0.60 V on its own axis
|   POWER clamp passes 1 mA (typ) near -0.55 V on its own axis
|   rising waveform, R_fixture 50, V_fixture 1.8: 20-80 % time 113ps typ, 179ps min, 78.9ps max; typ from 0.737 V to 1.8 V
|   rising waveform, R_fixture 50, V_fixture 0: 20-80 % time 248ps typ, 612ps min, 119ps max; typ from 0 V to 1.08 V
|   falling waveform, R_fixture 50, V_fixture 1.8: 20-80 % time 252ps typ, 609ps min, 137ps max; typ from 1.8 V to 0.737 V
|   falling waveform, R_fixture 50, V_fixture 0: 20-80 % time 136ps typ, 236ps min, 92.6ps max; typ from 1.08 V to 0 V
[POWER_clamp]
-1.8V     7.429A     8.065A     7.064A
-1.182V   1.663A     2.35A      1.259A
-1.164V   1.508A     2.193A     1.106A
-1.127V   1.206A     1.883A     813.3mA
-1.073V   782.1mA    1.435A     426.3mA
-1.036V   530.7mA    1.15A      232.5mA
-981.8mV  234.7mA    756.3mA    81.79mA
-909.1mV  52.86mA    331.4mA    24.54mA
-872.7mV  25.66mA    185.5mA    15.5mA
-818.2mV  11.27mA    62mA       10.15mA
-709.1mV  4.611mA    6.166mA    4.556mA
1.8V      101uA      43.59uA    177.4uA
[Pulldown]
-1.8V     -1.194mA   -708.4uA   -1.62mA
-1.364V   -2.427mA   -1.16mA    -4.962mA
-1.145V   -4.869mA   -1.705mA   -17.59mA
-818.2mV  -24.64mA   -5.097mA   -34.41mA
-545.5mV  -21.18mA   -13.06mA   -27.54mA
654.5mV   19.52mA    10.56mA    27.82mA
1.527V    26.09mA    12.74mA    39.54mA
2.345V    26.12mA    12.56mA    39.67mA
2.618V    25.84mA    3.762mA    39.51mA
2.782V    15.29mA    1.796mA    38.75mA
3.055V    2.769mA    903.4uA    6.807mA
3.545V    1.202mA    771.2uA    1.468mA
[Pullup]
-1.8V     2.751mA    2.282mA    2.931mA
-1.2V     7.642mA    4.475mA    10.93mA
-1.091V   13.62mA    6.537mA    25.15mA
-1.036V   20.45mA    8.342mA    44.85mA
-981.8mV  32.37mA    11.16mA    63.55mA
-927.3mV  44.36mA    15.62mA    67.08mA
-872.7mV  47.84mA    21.61mA    66.32mA
-763.6mV  44.16mA    27.09mA    59.88mA
54.55mV   -2.548mA   -1.463mA   -3.578mA
709.1mV   -21.68mA   -10.05mA   -32.93mA
2.127V    -27.28mA   -11.7mA    -43.28mA
3.545V    -25.07mA   -10.87mA   -38.77mA
[GND_clamp]
-1.8V     -794.1mA   -670.5mA   -980.8mA
-1.109V   -139.6mA   -162.6mA   -140.1mA
-1.073V   -112.8mA   -141.5mA   -105.3mA
-1.036V   -89.25mA   -122.4mA   -75.78mA
-1V       -69.85mA   -105.6mA   -53.4mA
-963.6mV  -54.51mA   -90.99mA   -38.26mA
-890.9mV  -31.22mA   -66.62mA   -21.22mA
-818.2mV  -14.77mA   -45.88mA   -13.44mA
-709.1mV  -3.952mA   -20.19mA   -6.104mA
-600mV    -982.9uA   -4.198mA   -1.476mA
-490.9mV  -187.6uA   -374.7uA   -215.1uA
1.764V    101uA      43.71uA    177.3uA
[Ramp]
dV/dt_f  0.6477255/0.2532352n  0.3824489/0.6206388n  0.7911889/0.1378326n
dV/dt_r  0.6666499/0.2486639n  0.3358717/0.6266542n  0.8391162/0.119778n
R_load = 50
[Rising Waveform]
R_fixture = 50
V_fixture = 1.8
V_fixture_min = 1.62
V_fixture_max = 1.89
0s        737.1mV    992.6mV    592.7mV
32ps      737.9mV    992.6mV    677.9mV
136ps     732.2mV    992.5mV    1.7V
192ps     717.9mV    992.5mV    1.872V
280ps     774mV      992.5mV    1.884V
384ps     1.403V     993.9mV    1.887V
488ps     1.758V     994.9mV    1.887V
912ps     1.798V     963.3mV    1.888V
1.248ns   1.798V     1.556V     1.888V
1.736ns   1.798V     1.616V     1.888V
[Rising Waveform]
R_fixture = 50
V_fixture = 0
V_fixture_min = 0
V_fixture_max = 0
0s        320.1nV    197.2nV    708nV
184ps     1.066mV    3.334uV    -15.92mV
344ps     -7.517mV   -6.636uV   1.056V
416ps     -23.59mV   -106.3uV   1.258V
512ps     14.45mV    -92.33uV   1.332V
768ps     769.4mV    1.935mV    1.363V
1.016ns   1.021V     -4.317mV   1.366V
1.344ns   1.075V     -2.609mV   1.366V
2.264ns   1.084V     461.2mV    1.366V
3.704ns   1.085V     539.2mV    1.366V
[Falling Waveform]
R_fixture = 50
V_fixture = 1.8
V_fixture_min = 1.62
V_fixture_max = 1.89
0s        1.799V     1.619V     1.888V
192ps     1.798V     1.619V     1.896V
376ps     1.809V     1.619V     888.4mV
448ps     1.817V     1.619V     698.7mV
544ps     1.753V     1.619V     628mV
824ps     1.006V     1.618V     595.5mV
1.064ns   784.3mV    1.622V     593.1mV
1.488ns   741.4mV    1.614V     592.7mV
2.448ns   737.2mV    1.07V      592.7mV
3.728ns   737.1mV    995.9mV    592.7mV
[Falling Waveform]
R_fixture = 50
V_fixture = 0
V_fixture_min = 0
V_fixture_max = 0
0s        1.085V     542.6mV    1.366V
40ps      1.085V     542.6mV    1.225V
168ps     1.103V     542.6mV    150.7mV
224ps     1.154V     542.6mV    27.22mV
280ps     1.014V     542.6mV    10.64mV
432ps     253.5mV    542.6mV    2.676mV
560ps     24.13mV    542.8mV    1.002mV
904ps     2.062mV    640.1mV    73.5uV
1.352ns   198.6uV    74.4mV     4.099uV
2.048ns   11.81uV    3.336mV    824.2nV
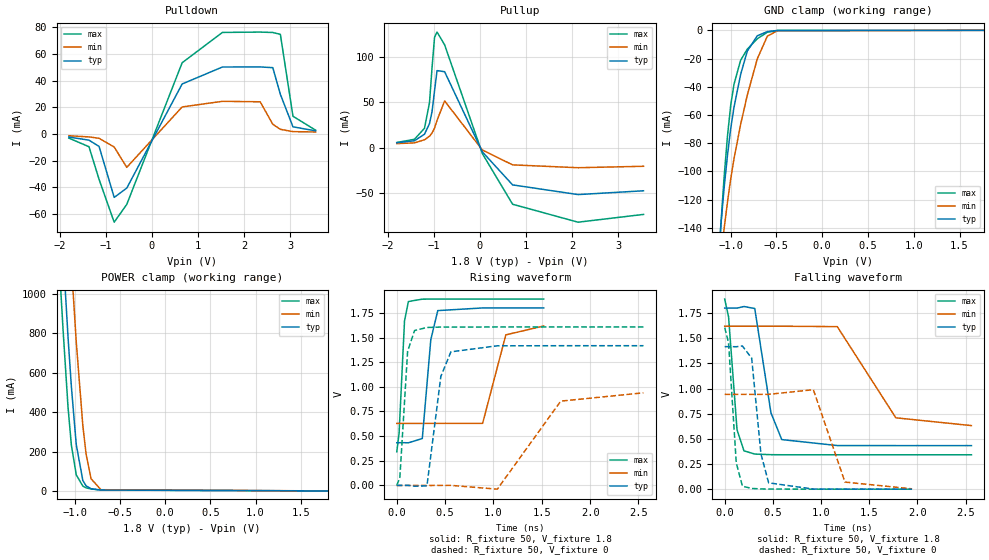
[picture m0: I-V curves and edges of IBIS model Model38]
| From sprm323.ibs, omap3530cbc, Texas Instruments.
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| Model based on original model for BQOMAPPROGIOCSHYFBPB_7LM
|   Sub model MODE00_PU_PD_OFF_1P8
[model]   Model38
|[Input Load]   PI
|[Output Drive] DS00
|Voltage   1.8V
|Mode   I/O
Model_type   I/O
Polarity   Non-Inverting
Enable   Active-Low
Vinl =  0.63
Vinh =  1.17
Cref =  15.0000pF
Rref =  100.0000M
Vref =  0V
Vmeas =  0.9
C_comp   0.8864943p   0.7714798p   1.034566p
[Model Spec]
Vinl   0.63   0.567   0.6615
Vinh   1.17   1.053   1.2285
[Temperature Range]   25   125   -40
[Voltage Range]   1.8   1.62   1.89
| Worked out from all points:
|   slope of the pulldown table from 0 to 0.27 V, typ, clamps not added: 15 ohm
|   slope of the pullup table from 0 to 0.27 V, typ, clamps not added: 12.7 ohm
|   GND clamp passes 1 mA (typ) near -0.61 V on its own axis
|   POWER clamp passes 1 mA (typ) near -0.56 V on its own axis
|   rising waveform, R_fixture 50, V_fixture 1.8: 20-80 % time 67.6ps typ, 113ps min, 44.7ps max; typ from 0.433 V to 1.8 V
|   rising waveform, R_fixture 50, V_fixture 0: 20-80 % time 114ps typ, 355ps min, 58.5ps max; typ from 0 V to 1.42 V
|   falling waveform, R_fixture 50, V_fixture 1.8: 20-80 % time 130ps typ, 342ps min, 70ps max; typ from 1.8 V to 0.433 V
|   falling waveform, R_fixture 50, V_fixture 0: 20-80 % time 90.2ps typ, 152ps min, 63.8ps max; typ from 1.42 V to 0 V
[POWER_clamp]
-1.8V     7.429A     8.065A     7.064A
-1.182V   1.663A     2.35A      1.259A
-1.164V   1.508A     2.193A     1.106A
-1.127V   1.206A     1.883A     813.2mA
-1.073V   782.1mA    1.435A     426.3mA
-1.036V   530.6mA    1.15A      232.4mA
-981.8mV  234.7mA    756.3mA    81.67mA
-909.1mV  52.8mA     331.4mA    24.39mA
-872.7mV  25.58mA    185.5mA    15.34mA
-818.2mV  11.18mA    61.99mA    9.987mA
-709.1mV  4.516mA    6.134mA    4.387mA
1.8V      470.6pA    2.239nA    626.3pA
[Pulldown]
-1.8V     -2.297mA   -1.36mA    -3.12mA
-1.364V   -4.671mA   -2.227mA   -9.575mA
-1.145V   -9.38mA    -3.274mA   -34.14mA
-818.2mV  -47.59mA   -9.8mA     -66.19mA
-545.5mV  -40.61mA   -25.06mA   -52.83mA
654.5mV   37.49mA    20.27mA    53.41mA
1.527V    50.21mA    24.47mA    76.15mA
2.345V    50.26mA    24.12mA    76.4mA
2.618V    49.72mA    7.252mA    76.1mA
2.782V    29.73mA    3.458mA    74.71mA
3.055V    5.35mA     1.737mA    13.28mA
3.545V    2.313mA    1.481mA    2.83mA
[Pullup]
-1.8V     5.219mA    4.328mA    5.561mA
-1.418V   7.442mA    5.119mA    9.078mA
-1.2V     14.66mA    8.527mA    21.17mA
-1.091V   26.27mA    12.48mA    49.44mA
-1.036V   39.59mA    15.94mA    87.83mA
-981.8mV  62.54mA    21.35mA    121.3mA
-927.3mV  84.62mA    29.89mA    127mA
-763.6mV  83.41mA    51.27mA    113mA
54.55mV   -4.816mA   -2.769mA   -6.75mA
709.1mV   -41.09mA   -19.06mA   -62.37mA
2.127V    -51.75mA   -22.2mA    -82.12mA
3.545V    -47.57mA   -20.61mA   -73.57mA
[GND_clamp]
-1.8V     -794.1mA   -670.5mA   -980.8mA
-1.109V   -139.6mA   -162.5mA   -140mA
-1.073V   -112.7mA   -141.5mA   -105.3mA
-1.036V   -89.23mA   -122.4mA   -75.75mA
-1V       -69.83mA   -105.6mA   -53.36mA
-963.6mV  -54.49mA   -90.99mA   -38.21mA
-890.9mV  -31.19mA   -66.62mA   -21.14mA
-818.2mV  -14.71mA   -45.88mA   -13.31mA
-709.1mV  -3.87mA    -20.18mA   -5.973mA
-600mV    -903.1uA   -4.176mA   -1.354mA
-490.9mV  -116.3uA   -342.2uA   -105.5uA
1.764V    389.6pA    119.4nA    561.5pA
[Ramp]
dV/dt_f  0.8488926/0.1305887n  0.6118541/0.3531357n  0.9680156/72.48521p
dV/dt_r  0.8841743/0.1143995n  0.5899317/0.3619187n   1.003989/59.25357p
R_load = 50
[Rising Waveform]
R_fixture = 50
V_fixture = 1.8
V_fixture_min = 1.62
V_fixture_max = 1.89
0s        433.2mV    628.7mV    341.8mV
24ps      433.5mV    628.7mV    531mV
80ps      433.5mV    628.7mV    1.668V
120ps     432.3mV    628.7mV    1.865V
264ps     476.1mV    628.7mV    1.889V
352ps     1.479V     629.1mV    1.89V
424ps     1.773V     629.5mV    1.89V
888ps     1.8V       629.8mV    1.89V
1.128ns   1.8V       1.527V     1.89V
1.52ns    1.8V       1.617V     1.89V
[Rising Waveform]
R_fixture = 50
V_fixture = 0
V_fixture_min = 0
V_fixture_max = 0
0s        199.7nV    132.6nV    425.9nV
32ps      337uV      2.324uV    81.56mV
112ps     1.812mV    3.194uV    1.36V
184ps     -7.564mV   71.81nV    1.571V
312ps     -4.28mV    -83.59uV   1.602V
456ps     1.106V     85.3uV     1.606V
560ps     1.355V     759.3uV    1.606V
1.04ns    1.416V     -37.62mV   1.607V
1.696ns   1.417V     855.1mV    1.607V
2.552ns   1.417V     939.3mV    1.607V
[Falling Waveform]
R_fixture = 50
V_fixture = 1.8
V_fixture_min = 1.62
V_fixture_max = 1.89
0s        1.8V       1.62V      1.89V
40ps      1.8V       1.62V      1.715V
128ps     1.8V       1.62V      589.4mV
200ps     1.816V     1.62V      381.3mV
312ps     1.796V     1.62V      349mV
480ps     759.1mV    1.62V      342.8mV
592ps     492.9mV    1.62V      342.1mV
1.168ns   433.6mV    1.616V     341.8mV
1.776ns   433.2mV    709.3mV    341.8mV
2.56ns    433.2mV    632.1mV    341.8mV
[Falling Waveform]
R_fixture = 50
V_fixture = 0
V_fixture_min = 0
V_fixture_max = 0
0s        1.417V     942.7mV    1.607V
40ps      1.417V     942.7mV    1.456V
120ps     1.416V     942.7mV    261.9mV
184ps     1.423V     942.7mV    29.86mV
280ps     1.303V     942.7mV    7.011mV
376ps     350.8mV    942.7mV    2.462mV
456ps     62.88mV    942.7mV    1.031mV
920ps     841.5uV    988.9mV    32.98uV
1.248ns   111uV      70.39mV    5.334uV
1.944ns   9.638uV    3.383mV    508.8nV
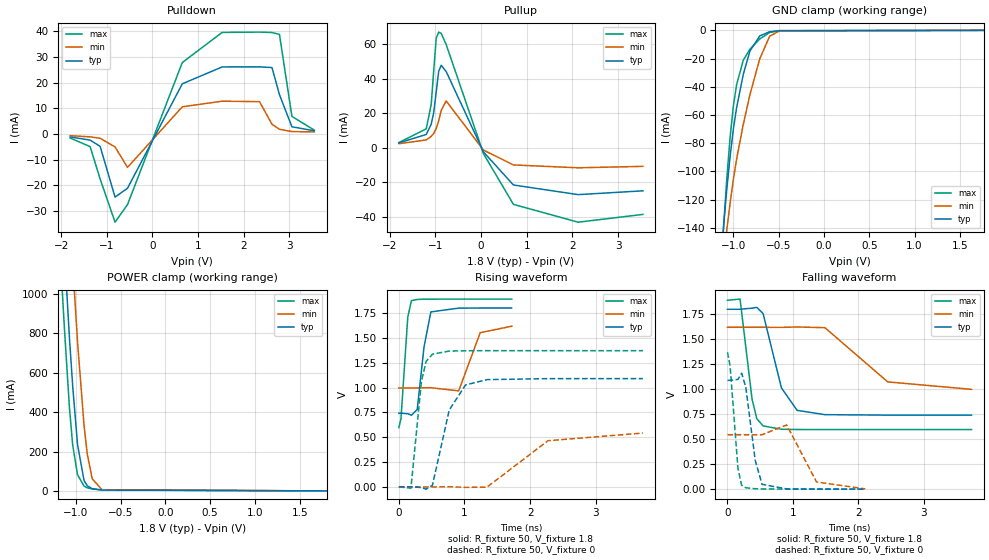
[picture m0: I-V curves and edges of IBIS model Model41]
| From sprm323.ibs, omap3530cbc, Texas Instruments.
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| Model based on original model for BQOMAPPROGIOCSHYFBPB_7LM
|   Sub model MODE10_PU_ON_1P8
[model]   Model41
|[Input Load]   PU
|[Output Drive] DS10
|Voltage   1.8V
|Mode   I/O
Model_type   I/O
Polarity   Non-Inverting
Enable   Active-Low
Vinl =  0.63
Vinh =  1.17
Cref =  15.0000pF
Rref =  100.0000M
Vref =  0V
Vmeas =  0.9
C_comp   0.8864943p   0.7714798p   1.034566p
[Model Spec]
Vinl   0.63   0.567   0.6615
Vinh   1.17   1.053   1.2285
[Temperature Range]   25   125   -40
[Voltage Range]   1.8   1.62   1.89
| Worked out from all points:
|   slope of the pulldown table from 0 to 0.27 V, typ, clamps not added: 28.9 ohm
|   slope of the pullup table from 0 to 0.27 V, typ, clamps not added: 24 ohm
|   GND clamp passes 1 mA (typ) near -0.60 V on its own axis
|   POWER clamp passes 1 mA (typ) near -0.55 V on its own axis
|   rising waveform, R_fixture 50, V_fixture 1.8: 20-80 % time 112ps typ, 178ps min, 78.5ps max; typ from 0.742 V to 1.8 V
|   rising waveform, R_fixture 50, V_fixture 0: 20-80 % time 248ps typ, 614ps min, 119ps max; typ from 0.002 V to 1.09 V
|   falling waveform, R_fixture 50, V_fixture 1.8: 20-80 % time 254ps typ, 610ps min, 137ps max; typ from 1.8 V to 0.742 V
|   falling waveform, R_fixture 50, V_fixture 0: 20-80 % time 137ps typ, 239ps min, 93.6ps max; typ from 1.09 V to 0.002 V
[POWER_clamp]
-1.8V     7.429A     8.065A     7.064A
-1.182V   1.663A     2.35A      1.259A
-1.164V   1.508A     2.193A     1.106A
-1.127V   1.206A     1.883A     813.3mA
-1.073V   782.1mA    1.435A     426.4mA
-1.036V   530.7mA    1.15A      232.5mA
-981.8mV  234.7mA    756.4mA    81.82mA
-909.1mV  52.91mA    331.4mA    24.57mA
-872.7mV  25.71mA    185.5mA    15.52mA
-818.2mV  11.31mA    62.04mA    10.16mA
-709.1mV  4.634mA    6.205mA    4.543mA
1.8V      403.3pA    2.083nA    554.5pA
[Pulldown]
-1.8V     -1.194mA   -708.4uA   -1.62mA
-1.364V   -2.428mA   -1.16mA    -4.962mA
-1.145V   -4.869mA   -1.705mA   -17.59mA
-818.2mV  -24.64mA   -5.097mA   -34.41mA
-545.5mV  -21.18mA   -13.06mA   -27.54mA
654.5mV   19.52mA    10.56mA    27.82mA
1.527V    26.09mA    12.74mA    39.54mA
2.345V    26.12mA    12.56mA    39.67mA
2.618V    25.84mA    3.762mA    39.51mA
2.782V    15.29mA    1.796mA    38.75mA
3.055V    2.769mA    903.4uA    6.807mA
3.545V    1.202mA    771.2uA    1.468mA
[Pullup]
-1.8V     2.751mA    2.282mA    2.931mA
-1.2V     7.642mA    4.475mA    10.93mA
-1.091V   13.62mA    6.537mA    25.15mA
-1.036V   20.45mA    8.342mA    44.85mA
-981.8mV  32.37mA    11.16mA    63.55mA
-927.3mV  44.36mA    15.62mA    67.08mA
-872.7mV  47.84mA    21.61mA    66.32mA
-763.6mV  44.16mA    27.09mA    59.88mA
54.55mV   -2.548mA   -1.463mA   -3.577mA
709.1mV   -21.68mA   -10.05mA   -32.93mA
2.127V    -27.28mA   -11.7mA    -43.28mA
3.545V    -25.07mA   -10.87mA   -38.77mA
[GND_clamp]
-1.8V     -794.1mA   -670.5mA   -980.8mA
-1.109V   -139.6mA   -162.6mA   -140.1mA
-1.073V   -112.8mA   -141.5mA   -105.3mA
-1.036V   -89.25mA   -122.4mA   -75.78mA
-1V       -69.85mA   -105.6mA   -53.39mA
-963.6mV  -54.51mA   -91mA      -38.25mA
-890.9mV  -31.23mA   -66.63mA   -21.22mA
-818.2mV  -14.77mA   -45.89mA   -13.43mA
-709.1mV  -3.956mA   -20.2mA    -6.107mA
-600mV    -995.8uA   -4.202mA   -1.492mA
-490.9mV  -212.7uA   -380.9uA   -249.1uA
1.764V    -5.644uA   14.27uA    -26.63uA
[Ramp]
dV/dt_f  0.6464817/0.2542271n  0.3810536/0.6214846n  0.7908681/0.1384542n
dV/dt_r  0.6684111/0.2486371n  0.3371206/0.6288283n  0.8400269/0.119496n
R_load = 50
[Rising Waveform]
R_fixture = 50
V_fixture = 1.8
V_fixture_min = 1.62
V_fixture_max = 1.89
0s        741.7mV    996.3mV    597.5mV
32ps      742.6mV    996.3mV    684.5mV
136ps     736.8mV    996.2mV    1.709V
192ps     722.3mV    996.2mV    1.874V
280ps     779.3mV    996.2mV    1.886V
384ps     1.411V     997.6mV    1.889V
488ps     1.761V     998.7mV    1.889V
912ps     1.799V     966.8mV    1.89V
1.24ns    1.8V       1.552V     1.89V
1.72ns    1.8V       1.617V     1.89V
[Rising Waveform]
R_fixture = 50
V_fixture = 0
V_fixture_min = 0
V_fixture_max = 0
0s        1.756mV    1.065mV    2.129mV
184ps     2.822mV    1.068mV    -12.05mV
344ps     -5.757mV   1.058mV    1.062V
416ps     -21.49mV   958.8uV    1.264V
512ps     17.84mV    973.5uV    1.336V
768ps     774.5mV    2.992mV    1.367V
1.016ns   1.026V     -3.255mV   1.37V
1.344ns   1.08V      -769.1uV   1.371V
2.272ns   1.09V      465.7mV    1.371V
3.72ns    1.09V      542.8mV    1.371V
[Falling Waveform]
R_fixture = 50
V_fixture = 1.8
V_fixture_min = 1.62
V_fixture_max = 1.89
0s        1.8V       1.62V      1.89V
192ps     1.8V       1.62V      1.902V
376ps     1.811V     1.62V      899.3mV
448ps     1.819V     1.62V      706.3mV
544ps     1.757V     1.62V      634.1mV
824ps     1.014V     1.619V     600.7mV
1.064ns   789.6mV    1.623V     598.1mV
1.488ns   746.4mV    1.616V     597.5mV
2.448ns   741.9mV    1.074V     597.5mV
3.728ns   741.8mV    999.6mV    597.5mV
[Falling Waveform]
R_fixture = 50
V_fixture = 0
V_fixture_min = 0
V_fixture_max = 0
0s        1.09V      546.1mV    1.371V
40ps      1.09V      546.1mV    1.232V
160ps     1.099V     546.1mV    208.5mV
216ps     1.161V     546.1mV    40.09mV
280ps     1.02V      546.1mV    15.8mV
424ps     288.6mV    546.1mV    6.035mV
528ps     50.22mV    546.2mV    3.965mV
904ps     4.516mV    643.5mV    2.27mV
1.36ns    2.056mV    73.87mV    2.138mV
2.104ns   1.775mV    4.398mV    2.129mV
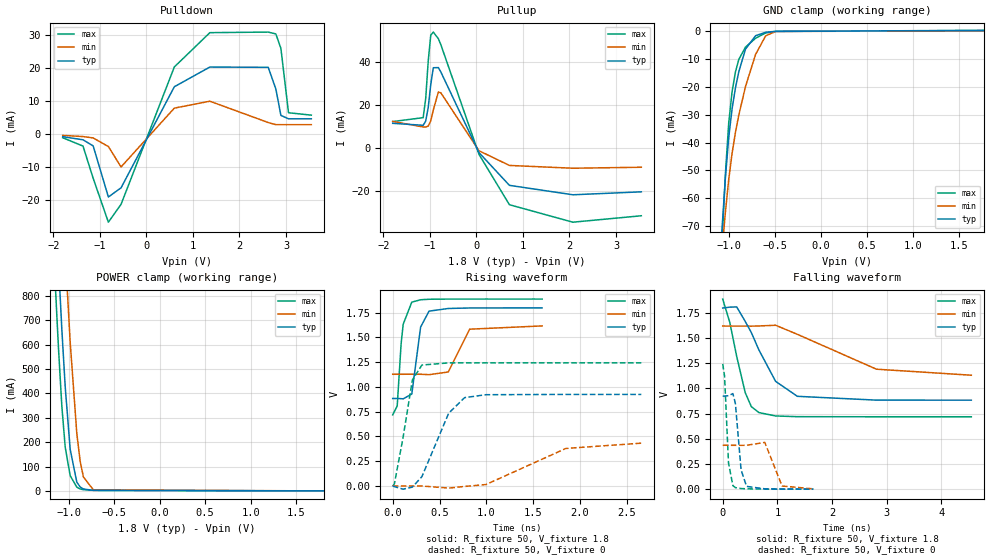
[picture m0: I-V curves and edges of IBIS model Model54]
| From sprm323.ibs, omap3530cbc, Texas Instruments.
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| Model based on original model for BQ0228CS_7LM
|   Sub model BQ0228CS_7LM_PD_ON_1P8
[model]   Model54
|[Input Load]   PD
|[Output Drive]
|Voltage   1.8V
|Mode   I/O
Model_type   I/O
Polarity   Non-Inverting
Enable   Active-Low
Vinl =  0.63
Vinh =  1.17
Cref =  15.0000pF
Rref =  100.0000M
Vref =  0V
Vmeas =  0.9
C_comp   0.7419724p   0.6186122p   0.9021994p
[Model Spec]
Vinl   0.63   0.567   0.6615
Vinh   1.17   1.053   1.2285
[Temperature Range]   25   125   -40
[Voltage Range]   1.8   1.62   1.89
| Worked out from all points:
|   slope of the pulldown table from 0 to 0.27 V, typ, clamps not added: 37.2 ohm
|   slope of the pullup table from 0 to 0.27 V, typ, clamps not added: 30.1 ohm
|   GND clamp passes 1 mA (typ) near -0.66 V on its own axis
|   POWER clamp passes 1 mA (typ) near -0.62 V on its own axis
|   rising waveform, R_fixture 50, V_fixture 1.8: 20-80 % time 71.3ps typ, 114ps min, 55.3ps max; typ from 0.884 V to 1.8 V
|   rising waveform, R_fixture 50, V_fixture 0: 20-80 % time 254ps typ, 609ps min, 137ps max; typ from 0 V to 0.925 V
|   falling waveform, R_fixture 50, V_fixture 1.8: 20-80 % time 508ps typ, 1.12ns min, 285ps max; typ from 1.8 V to 0.883 V
|   falling waveform, R_fixture 50, V_fixture 0: 20-80 % time 88ps typ, 148ps min, 63ps max; typ from 0.925 V to 0 V
[POWER_clamp]
-1.8V     6.299A     6.506A     6.196A
-1.164V   1.344A     1.893A     994.1mA
-1.127V   1.063A     1.63A      711.8mA
-1.109V   925.8mA    1.498A     579.2mA
-1.073V   661.6mA    1.236A     346.9mA
-1.036V   426.8mA    976.8mA    179.1mA
-981.8mV  170.9mA    611.1mA    62.77mA
-909.1mV  36.26mA    236.5mA    15.53mA
-872.7mV  16.51mA    123mA      7.962mA
-836.4mV  7.937mA    57.21mA    5.243mA
-727.3mV  2.344mA    4.356mA    2.387mA
1.8V      125.3uA    51.97uA    219uA
[Pulldown]
-1.8V     -923.4uA   -546.6uA   -1.251mA
-1.364V   -1.871mA   -894.2uA   -3.779mA
-1.145V   -3.734mA   -1.313mA   -13.56mA
-818.2mV  -19.23mA   -3.925mA   -26.88mA
-545.5mV  -16.45mA   -10.11mA   -21.46mA
600mV     14.23mA    7.738mA    20.23mA
1.364V    20.2mA     9.834mA    30.64mA
2.618V    20.12mA    3.366mA    30.81mA
2.782V    13.57mA    2.716mA    30.26mA
2.891V    5.527mA    2.714mA    25.86mA
3.055V    4.494mA    2.712mA    6.327mA
3.545V    4.488mA    2.709mA    5.61mA
[Pullup]
-1.8V     11.56mA    12.44mA    12.38mA
-1.145V   10.65mA    9.865mA    14.2mA
-1.091V   12.57mA    9.798mA    23mA
-1.036V   19.01mA    10.29mA    40.58mA
-981.8mV  29.64mA    12.69mA    52.61mA
-927.3mV  37.42mA    17.78mA    54mA
-818.2mV  37.48mA    26.16mA    50.92mA
-763.6mV  35.38mA    25.7mA     48.06mA
54.55mV   -2.036mA   -1.184mA   -2.864mA
709.1mV   -17.28mA   -8.025mA   -26.29mA
2.073V    -21.67mA   -9.32mA    -34.42mA
3.545V    -20.3mA    -8.865mA   -31.43mA
[GND_clamp]
-1.8V     -645.6mA   -500mA     -849.8mA
-1.073V   -71.08mA   -78.89mA   -76.42mA
-1.036V   -52.54mA   -64.93mA   -51.21mA
-1V       -38.13mA   -53.23mA   -32.98mA
-963.6mV  -27.9mA    -43.88mA   -21.73mA
-927.3mV  -20.45mA   -36.39mA   -14.71mA
-890.9mV  -14.64mA   -30.18mA   -10.24mA
-818.2mV  -6.518mA   -19.93mA   -5.792mA
-709.1mV  -1.723mA   -8.439mA   -2.636mA
-600mV    -489.4uA   -1.77mA    -731.6uA
-490.9mV  -149.5uA   -195.2uA   -195.1uA
1.764V    125uA      52.51uA    217.2uA
[Ramp]
dV/dt_f  0.5592835/0.5180107n  0.3006497/1.159861n   0.7140813/0.2897448n
dV/dt_r  0.5767914/0.2620335n  0.2745184/0.6379888n  0.7741775/0.1409942n
R_load = 50
[Rising Waveform]
R_fixture = 50
V_fixture = 1.8
V_fixture_min = 1.62
V_fixture_max = 1.89
0s        883.5mV    1.128V     718.5mV
48ps      883.6mV    1.128V     807.7mV
90ps      881.7mV    1.128V     1.438V
112ps     879.8mV    1.128V     1.633V
204ps     928.6mV    1.129V     1.856V
298ps     1.604V     1.128V     1.88V
388ps     1.765V     1.124V     1.885V
594ps     1.792V     1.151V     1.887V
822ps     1.797V     1.583V     1.887V
1.596ns   1.798V     1.616V     1.887V
[Rising Waveform]
R_fixture = 50
V_fixture = 0
V_fixture_min = 0
V_fixture_max = 0
0s        159.7nV    66.05nV    359.3nV
18ps      -6.1mV     -2.367uV   22.41mV
110ps     -31.69mV   57.3uV     485.9mV
210ps     -10.92mV   236.5uV    1.07V
312ps     94.94mV    160.9uV    1.221V
598ps     735.1mV    -20.75mV   1.243V
768ps     892mV      -4.366mV   1.243V
996ps     921.6mV    14.93mV    1.243V
1.85ns    924.6mV    379.3mV    1.243V
2.656ns   924.6mV    432.5mV    1.243V
[Falling Waveform]
R_fixture = 50
V_fixture = 1.8
V_fixture_min = 1.62
V_fixture_max = 1.89
0s        1.798V     1.619V     1.887V
130ps     1.807V     1.619V     1.655V
256ps     1.809V     1.619V     1.317V
412ps     1.665V     1.619V     958mV
524ps     1.554V     1.618V     819mV
662ps     1.382V     1.62V      760.4mV
968ps     1.07V      1.627V     726.6mV
1.366ns   921.6mV    1.537V     719.6mV
2.812ns   883.8mV    1.191V     718.5mV
4.548ns   883.5mV    1.131V     718.5mV
[Falling Waveform]
R_fixture = 50
V_fixture = 0
V_fixture_min = 0
V_fixture_max = 0
0s        924.6mV    435.8mV    1.243V
34ps      924mV      435.9mV    1.122V
106ps     927.9mV    435.7mV    260.8mV
186ps     948.8mV    435.4mV    35.86mV
232ps     850.6mV    435.4mV    15.15mV
336ps     192.2mV    435.3mV    6.327mV
436ps     27.78mV    435.4mV    3.329mV
770ps     3.297mV    464.1mV    962.6uV
1.086ns   1.571mV    31.38mV    211.9uV
1.658ns   419.3uV    3.254mV    19.95uV
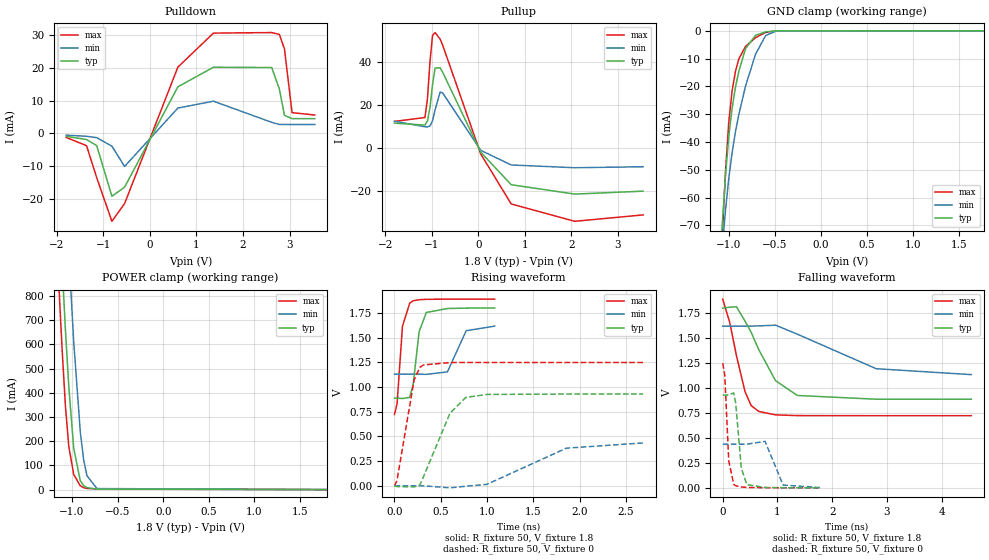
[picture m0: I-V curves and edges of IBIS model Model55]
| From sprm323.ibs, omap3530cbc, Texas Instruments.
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| Model based on original model for BQ0228CS_7LM
|   Sub model 0228CS_PD_PU_OFF_1P8
[model]   Model55
|[Input Load]   PI
|[Output Drive]
|Voltage   1.8V
|Mode   I/O
Model_type   I/O
Polarity   Non-Inverting
Enable   Active-Low
Vinl =  0.63
Vinh =  1.17
Cref =  15.0000pF
Rref =  100.0000M
Vref =  0V
Vmeas =  0.9
C_comp   0.7419724p   0.6186122p   0.9021994p
[Model Spec]
Vinl   0.63   0.567   0.6615
Vinh   1.17   1.053   1.2285
[Temperature Range]   25   125   -40
[Voltage Range]   1.8   1.62   1.89
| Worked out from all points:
|   slope of the pulldown table from 0 to 0.27 V, typ, clamps not added: 37.2 ohm
|   slope of the pullup table from 0 to 0.27 V, typ, clamps not added: 30.1 ohm
|   GND clamp passes 1 mA (typ) near -0.67 V on its own axis
|   POWER clamp passes 1 mA (typ) near -0.64 V on its own axis
|   rising waveform, R_fixture 50, V_fixture 1.8: 20-80 % time 71.2ps typ, 113ps min, 54.6ps max; typ from 0.887 V to 1.8 V
|   rising waveform, R_fixture 50, V_fixture 0: 20-80 % time 255ps typ, 610ps min, 137ps max; typ from 0 V to 0.929 V
|   falling waveform, R_fixture 50, V_fixture 1.8: 20-80 % time 507ps typ, 1.11ns min, 284ps max; typ from 1.8 V to 0.887 V
|   falling waveform, R_fixture 50, V_fixture 0: 20-80 % time 89.4ps typ, 149ps min, 64.3ps max; typ from 0.929 V to 0 V
[POWER_clamp]
-1.8V     6.299A     6.506A     6.196A
-1.164V   1.344A     1.893A     994.1mA
-1.127V   1.063A     1.63A      711.7mA
-1.109V   925.8mA    1.498A     579.2mA
-1.073V   661.5mA    1.236A     346.8mA
-1.036V   426.8mA    976.8mA    179mA
-981.8mV  170.8mA    611.1mA    62.6mA
-909.1mV  36.18mA    236.5mA    15.33mA
-872.7mV  16.41mA    123mA      7.755mA
-836.4mV  7.825mA    57.2mA     5.033mA
-727.3mV  2.223mA    4.32mA     2.172mA
1.8V      5.377nA    2.929nA    8.929nA
[Pulldown]
-1.8V     -923.4uA   -546.6uA   -1.251mA
-1.364V   -1.871mA   -894.2uA   -3.779mA
-1.145V   -3.734mA   -1.313mA   -13.56mA
-818.2mV  -19.23mA   -3.924mA   -26.88mA
-545.5mV  -16.45mA   -10.11mA   -21.46mA
600mV     14.23mA    7.738mA    20.24mA
1.364V    20.2mA     9.834mA    30.64mA
2.618V    20.12mA    3.366mA    30.81mA
2.782V    13.57mA    2.716mA    30.25mA
2.891V    5.527mA    2.714mA    25.85mA
3.055V    4.494mA    2.712mA    6.326mA
3.545V    4.488mA    2.709mA    5.61mA
[Pullup]
-1.8V     11.56mA    12.44mA    12.38mA
-1.145V   10.65mA    9.865mA    14.2mA
-1.091V   12.57mA    9.798mA    22.99mA
-1.036V   19.01mA    10.29mA    40.58mA
-981.8mV  29.64mA    12.69mA    52.61mA
-927.3mV  37.42mA    17.78mA    54mA
-818.2mV  37.48mA    26.16mA    50.92mA
-763.6mV  35.38mA    25.7mA     48.06mA
54.55mV   -2.036mA   -1.184mA   -2.863mA
709.1mV   -17.28mA   -8.025mA   -26.29mA
2.073V    -21.67mA   -9.32mA    -34.42mA
3.545V    -20.3mA    -8.865mA   -31.43mA
[GND_clamp]
-1.8V     -645.6mA   -500mA     -849.8mA
-1.073V   -71.04mA   -78.87mA   -76.37mA
-1.036V   -52.49mA   -64.91mA   -51.16mA
-1V       -38.08mA   -53.21mA   -32.92mA
-963.6mV  -27.84mA   -43.85mA   -21.66mA
-927.3mV  -20.38mA   -36.36mA   -14.61mA
-890.9mV  -14.57mA   -30.15mA   -10.12mA
-818.2mV  -6.416mA   -19.89mA   -5.619mA
-709.1mV  -1.607mA   -8.383mA   -2.459mA
-600mV    -378.7uA   -1.711mA   -563.3uA
-490.9mV  -49.84uA   -141.5uA   -43.56uA
1.764V    4.447nA    18.15nA    4.794nA
[Ramp]
dV/dt_f  0.5594553/0.5179695n  0.3003856/1.157517n   0.7162263/0.2903393n
dV/dt_r  0.5794347/0.2628209n  0.2755412/0.6394118n  0.7771672/0.1411852n
R_load = 50
[Rising Waveform]
R_fixture = 50
V_fixture = 1.8
V_fixture_min = 1.62
V_fixture_max = 1.89
0s        887.2mV    1.131V     722.4mV
28ps      887.3mV    1.131V     830.5mV
86ps      883.9mV    1.131V     1.615V
164ps     895.6mV    1.131V     1.848V
202ps     1.029V     1.131V     1.874V
266ps     1.561V     1.131V     1.884V
344ps     1.755V     1.128V     1.888V
572ps     1.795V     1.154V     1.89V
774ps     1.799V     1.57V      1.89V
1.082ns   1.8V       1.617V     1.89V
[Rising Waveform]
R_fixture = 50
V_fixture = 0
V_fixture_min = 0
V_fixture_max = 0
0s        161.6nV    66.55nV    365.1nV
26ps      -7.494mV   235.1nV    49.08mV
212ps     -11.01mV   236.6uV    1.072V
274ps     7.734mV    256.1uV    1.2V
314ps     94.82mV    161uV      1.224V
600ps     736.6mV    -20.76mV   1.248V
770ps     894.6mV    -4.395mV   1.248V
998ps     925.1mV    14.89mV    1.248V
1.856ns   928.8mV    381mV      1.248V
2.684ns   928.9mV    434.2mV    1.248V
[Falling Waveform]
R_fixture = 50
V_fixture = 1.8
V_fixture_min = 1.62
V_fixture_max = 1.89
0s        1.8V       1.62V      1.89V
128ps     1.809V     1.62V      1.656V
252ps     1.813V     1.62V      1.321V
408ps     1.669V     1.62V      962.8mV
520ps     1.557V     1.62V      824mV
660ps     1.383V     1.622V     764.8mV
966ps     1.073V     1.629V     730.9mV
1.364ns   925.3mV    1.539V     723.6mV
2.806ns   887.6mV    1.193V     722.4mV
4.544ns   887.3mV    1.134V     722.4mV
[Falling Waveform]
R_fixture = 50
V_fixture = 0
V_fixture_min = 0
V_fixture_max = 0
0s        929mV      437.5mV    1.248V
38ps      928.4mV    437.6mV    1.128V
110ps     932.2mV    437.4mV    270.8mV
202ps     950mV      437.1mV    34.39mV
236ps     855.3mV    437.1mV    21.1mV
340ps     198mV      437mV      9.046mV
440ps     32.43mV    437.1mV    4.353mV
774ps     4.279mV    465.7mV    1.054mV
1.104ns   1.696mV    27.94mV    208uV
1.774ns   320.5uV    3.248mV    12.35uV
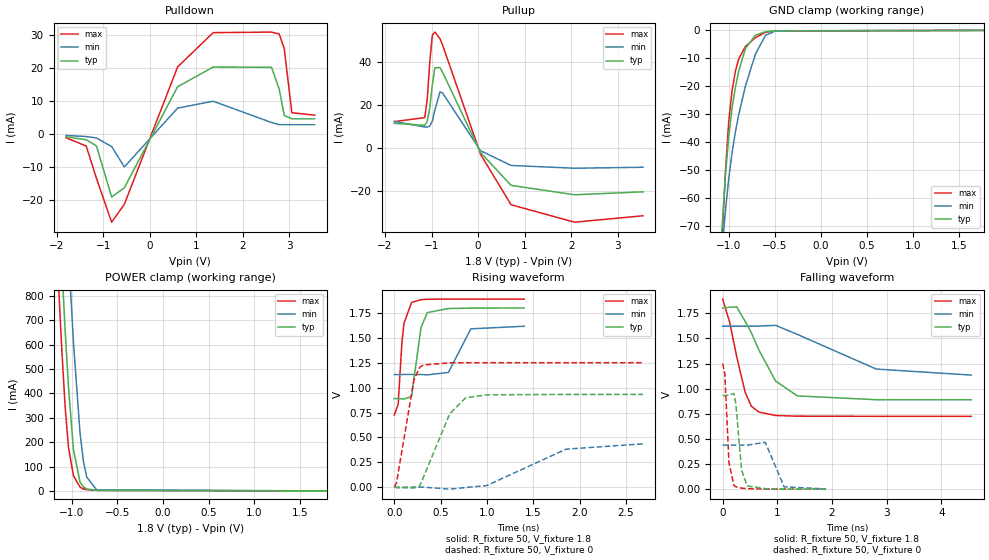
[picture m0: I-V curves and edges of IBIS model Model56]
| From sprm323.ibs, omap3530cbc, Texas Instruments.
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| Model based on original model for BQ0228CS_7LM
|   Sub model BQ0228CS_7LM_PU_ON_1P8
[model]   Model56
|[Input Load]   PU
|[Output Drive]
|Voltage   1.8V
|Mode   I/O
Model_type   I/O
Polarity   Non-Inverting
Enable   Active-Low
Vinl =  0.63
Vinh =  1.17
Cref =  15.0000pF
Rref =  100.0000M
Vref =  0V
Vmeas =  0.9
C_comp   0.7419724p   0.6186122p   0.9021994p
[Model Spec]
Vinl   0.63   0.567   0.6615
Vinh   1.17   1.053   1.2285
[Temperature Range]   25   125   -40
[Voltage Range]   1.8   1.62   1.89
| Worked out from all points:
|   slope of the pulldown table from 0 to 0.27 V, typ, clamps not added: 37.2 ohm
|   slope of the pullup table from 0 to 0.27 V, typ, clamps not added: 30.1 ohm
|   GND clamp passes 1 mA (typ) near -0.66 V on its own axis
|   POWER clamp passes 1 mA (typ) near -0.62 V on its own axis
|   rising waveform, R_fixture 50, V_fixture 1.8: 20-80 % time 70.9ps typ, 113ps min, 54.2ps max; typ from 0.89 V to 1.8 V
|   rising waveform, R_fixture 50, V_fixture 0: 20-80 % time 255ps typ, 611ps min, 137ps max; typ from 0.002 V to 0.932 V
|   falling waveform, R_fixture 50, V_fixture 1.8: 20-80 % time 508ps typ, 1.11ns min, 285ps max; typ from 1.8 V to 0.89 V
|   falling waveform, R_fixture 50, V_fixture 0: 20-80 % time 89.4ps typ, 149ps min, 64.6ps max; typ from 0.932 V to 0.002 V
[POWER_clamp]
-1.8V     6.299A     6.506A     6.196A
-1.164V   1.344A     1.893A     994.1mA
-1.127V   1.063A     1.63A      711.8mA
-1.109V   925.8mA    1.498A     579.2mA
-1.073V   661.6mA    1.236A     346.9mA
-1.036V   426.8mA    976.9mA    179.1mA
-981.8mV  170.9mA    611.1mA    62.75mA
-909.1mV  36.27mA    236.5mA    15.5mA
-872.7mV  16.52mA    123mA      7.924mA
-836.4mV  7.941mA    57.24mA    5.199mA
-727.3mV  2.335mA    4.382mA    2.326mA
1.8V      4.506nA    2.551nA    7.525nA
[Pulldown]
-1.8V     -923.4uA   -546.6uA   -1.251mA
-1.364V   -1.871mA   -894.2uA   -3.779mA
-1.145V   -3.734mA   -1.313mA   -13.56mA
-818.2mV  -19.23mA   -3.924mA   -26.88mA
-545.5mV  -16.45mA   -10.11mA   -21.46mA
600mV     14.23mA    7.738mA    20.24mA
1.364V    20.2mA     9.834mA    30.64mA
2.618V    20.12mA    3.366mA    30.81mA
2.782V    13.57mA    2.716mA    30.25mA
2.891V    5.528mA    2.714mA    25.85mA
3.055V    4.494mA    2.712mA    6.327mA
3.545V    4.488mA    2.709mA    5.61mA
[Pullup]
-1.8V     11.56mA    12.44mA    12.38mA
-1.145V   10.65mA    9.865mA    14.2mA
-1.091V   12.57mA    9.798mA    23mA
-1.036V   19.01mA    10.29mA    40.58mA
-981.8mV  29.64mA    12.69mA    52.61mA
-927.3mV  37.42mA    17.78mA    54mA
-818.2mV  37.48mA    26.16mA    50.92mA
-763.6mV  35.38mA    25.7mA     48.06mA
54.55mV   -2.036mA   -1.184mA   -2.863mA
709.1mV   -17.28mA   -8.025mA   -26.29mA
2.073V    -21.67mA   -9.32mA    -34.42mA
3.545V    -20.3mA    -8.865mA   -31.43mA
[GND_clamp]
-1.8V     -645.6mA   -500mA     -849.8mA
-1.073V   -71.06mA   -78.88mA   -76.39mA
-1.036V   -52.52mA   -64.92mA   -51.19mA
-1V       -38.11mA   -53.22mA   -32.96mA
-963.6mV  -27.87mA   -43.86mA   -21.7mA
-927.3mV  -20.42mA   -36.37mA   -14.67mA
-890.9mV  -14.61mA   -30.16mA   -10.19mA
-818.2mV  -6.479mA   -19.91mA   -5.732mA
-709.1mV  -1.688mA   -8.413mA   -2.583mA
-600mV    -464.8uA   -1.747mA   -696.1uA
-490.9mV  -144.3uA   -181.2uA   -190.7uA
1.764V    -5.54uA    14.04uA    -26.2uA
[Ramp]
dV/dt_f  0.5575918/0.5186786n  0.2993867/1.157238n   0.7141006/0.2907539n
dV/dt_r  0.5793047/0.2627233n  0.2756474/0.639405n   0.7758268/0.1409983n
R_load = 50
[Rising Waveform]
R_fixture = 50
V_fixture = 1.8
V_fixture_min = 1.62
V_fixture_max = 1.89
0s        890.2mV    1.132V     725.8mV
42ps      890.3mV    1.132V     835.3mV
82ps      888.4mV    1.132V     1.451V
104ps     886.4mV    1.133V     1.645V
186ps     911.3mV    1.133V     1.856V
288ps     1.603V     1.132V     1.884V
356ps     1.754V     1.129V     1.888V
584ps     1.795V     1.153V     1.89V
826ps     1.799V     1.591V     1.89V
1.402ns   1.8V       1.617V     1.89V
[Rising Waveform]
R_fixture = 50
V_fixture = 0
V_fixture_min = 0
V_fixture_max = 0
0s        2.005mV    1.162mV    2.526mV
24ps      -5.004mV   1.162mV    46.62mV
212ps     -6.246mV   1.398mV    1.078V
274ps     12.49mV    1.416mV    1.204V
314ps     99.72mV    1.32mV     1.228V
600ps     741.1mV    -19.11mV   1.25V
770ps     898.7mV    -2.247mV   1.251V
998ps     928.7mV    17.06mV    1.251V
1.854ns   932.2mV    382.7mV    1.251V
2.684ns   932.3mV    436.2mV    1.251V
[Falling Waveform]
R_fixture = 50
V_fixture = 1.8
V_fixture_min = 1.62
V_fixture_max = 1.89
0s        1.8V       1.62V      1.89V
130ps     1.809V     1.62V      1.658V
256ps     1.813V     1.62V      1.32V
412ps     1.668V     1.62V      963.7mV
524ps     1.557V     1.62V      826.5mV
662ps     1.385V     1.622V     768.1mV
968ps     1.076V     1.629V     734.2mV
1.366ns   928.4mV    1.539V     727mV
2.808ns   890.5mV    1.195V     725.8mV
4.546ns   890.3mV    1.135V     725.8mV
[Falling Waveform]
R_fixture = 50
V_fixture = 0
V_fixture_min = 0
V_fixture_max = 0
0s        932.4mV    439.5mV    1.251V
40ps      931.8mV    439.6mV    1.15V
116ps     935.9mV    439.4mV    263.3mV
208ps     952mV      439.1mV    38.24mV
242ps     848.5mV    439.1mV    25.48mV
346ps     194.4mV    439mV      12.77mV
446ps     35.35mV    439.2mV    7.255mV
780ps     6.913mV    467.2mV    3.618mV
1.124ns   3.773mV    25.46mV    2.725mV
1.888ns   2.251mV    4.412mV    2.534mV
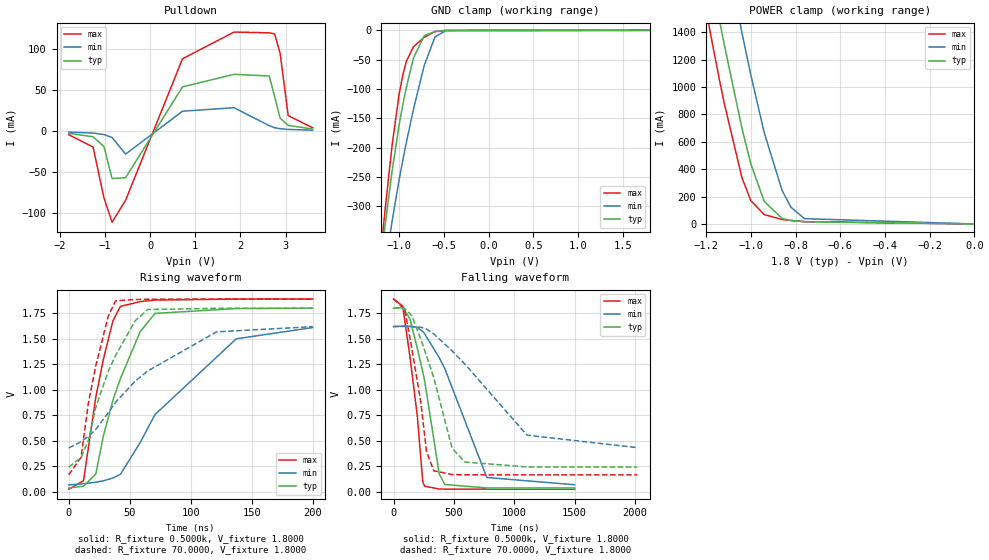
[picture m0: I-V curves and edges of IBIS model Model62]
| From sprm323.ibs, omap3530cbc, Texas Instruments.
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| Model based on original model for BQ0245S_7LM
|   Sub model BQ0245S_7LM_FA_ST
[model]   Model62
|[Input Load]
|[Output Drive] STANDARD
|Voltage   1.8000V
|Mode   I/O_OPEN_DRAIN
Model_type   I/O_open_drain
Polarity   Non-Inverting
Enable   Active-Low
Vinl =   0.6615V
Vinh =   1.0530V
Vmeas =   0.9000V
Cref =  400pF
Rref =  70.0000
Vref =  1.800V
C_comp   27.0438pF   15.4231pF   39.2246pF
[Temperature Range]   25.0000   0.1250k   -40.0000
[Voltage Range]   1.8000V   1.6200V   1.8900V
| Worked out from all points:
|   slope of the pulldown table from 0 to 0.27 V, typ, clamps not added: 11.1 ohm
|   GND clamp passes 1 mA (typ) near -0.56 V on its own axis
|   POWER clamp passes 1 mA (typ) near -0.50 V on its own axis
|   rising waveform, R_fixture 0.5000k, V_fixture 1.8000: 20-80 % time 27.9ns typ, 58.5ns min, 16.4ns max; typ from 0.036 V to 1.8 V
|   rising waveform, R_fixture 70.0000, V_fixture 1.8000: 20-80 % time 27.9ns typ, 62.4ns min, 15.9ns max; typ from 0.241 V to 1.8 V
|   falling waveform, R_fixture 0.5000k, V_fixture 1.8000: 20-80 % time 167ns typ, 302ns min, 108ns max; typ from 1.8 V to 0.036 V
|   falling waveform, R_fixture 70.0000, V_fixture 1.8000: 20-80 % time 225ns typ, 493ns min, 131ns max; typ from 1.8 V to 0.241 V
[Pulldown]
-1.8V     -2.862mA   -1.367mA   -4.523mA
-1.26V    -7.08mA    -2.581mA   -19.59mA
-1.02V    -18.93mA   -4.306mA   -81.43mA
-840mV    -57.82mA   -8.011mA   -110.8mA
-540mV    -56.75mA   -28.1mA    -84.08mA
720mV     53.54mA    24mA       87.7mA
1.86V     68.8mA     28.25mA    120.1mA
2.64V     66.74mA    6.42mA     119.2mA
2.76V     41.71mA    3.92mA     117.9mA
2.88V     15.63mA    2.762mA    94.5mA
3.06V     6.743mA    1.889mA    18.68mA
3.6V      2.323mA    952uA      3.89mA
[GND_clamp]
-1.8V     -1.221A    -1.151A    -1.363A
-1.2V     -386.5mA   -449.7mA   -370.2mA
-1.16V    -335.5mA   -406.8mA   -309.4mA
-1.08V    -240.2mA   -325.8mA   -196.3mA
-1V       -160.3mA   -253.8mA   -107.7mA
-960mV    -127.1mA   -221.5mA   -76.33mA
-920mV    -97.28mA   -191.1mA   -52.71mA
-840mV    -46.78mA   -134.3mA   -27.94mA
-720mV    -9.253mA   -59.82mA   -11.79mA
-600mV    -1.888mA   -11.35mA   -2.27mA
-480mV    -137.6uA   -650.3uA   -84.11uA
1.8V      510.5nA    3.196uA    487.6nA
[POWER_clamp]
-1.8V     7.644A     8.363A     7.23A
-1.2V     2.004A     2.755A     1.56A
-1.18V    1.829A     2.578A     1.386A
-1.14V    1.486A     2.23A      1.05A
-1.12V    1.32A      2.059A     889mA
-1.04V    700.2mA    1.398A     339.6mA
-1V       439.3mA    1.088A     170.8mA
-940mV    164.6mA    666.7mA    68.12mA
-860mV    40.26mA    244.2mA    32.15mA
-820mV    25.73mA    121.5mA    25.04mA
-760mV    16.31mA    38.76mA    16.75mA
0V        510.5nA    462.5nA    537.3nA
[Ramp]
dV/dt_r   0.1397m/96.2792n   0.1238m/40.6737n   0.1707m/56.2794n
dV/dt_f   1.0585/0.1658u   0.9315/0.2992u   1.1195/0.1067u
R_load = 0.5000k
[Rising Waveform]
R_fixture = 0.5000k
V_fixture = 1.8000
V_fixture_min = 1.6200
V_fixture_max = 1.8900
0s        35.51mV    65.61mV    23.9mV
12.12ns   52.87mV    76.79mV    106.9mV
22.22ns   173.3mV    92.19mV    927.5mV
28.28ns   538.9mV    105.8mV    1.291V
36.36ns   901.5mV    133.8mV    1.681V
42.42ns   1.11V      169.7mV    1.818V
58.59ns   1.569V     480.7mV    1.865V
70.71ns   1.749V     755.8mV    1.88V
137.4ns   1.797V     1.5V       1.89V
200ns     1.8V       1.61V      1.89V
[Rising Waveform]
R_fixture = 70.0000
V_fixture = 1.8000
V_fixture_min = 1.6200
V_fixture_max = 1.8900
0s        241.2mV    428.2mV    164.3mV
10.1ns    332.8mV    489.7mV    336mV
16.16ns   506.1mV    542.6mV    871.9mV
22.22ns   827.4mV    611.9mV    1.236V
32.32ns   1.179V     772.6mV    1.718V
38.38ns   1.335V     875.5mV    1.872V
54.55ns   1.677V     1.085V     1.886V
64.65ns   1.787V     1.183V     1.888V
121.2ns   1.799V     1.568V     1.89V
200ns     1.8V       1.619V     1.89V
[Falling Waveform]
R_fixture = 0.5000k
V_fixture = 1.8000
V_fixture_min = 1.6200
V_fixture_max = 1.8900
0s        1.8V       1.62V      1.89V
75.76ns   1.808V     1.625V     1.822V
136.4ns   1.695V     1.624V     1.324V
197ns     1.409V     1.61V      742.8mV
242.4ns   1.173V     1.571V     95.51mV
257.6ns   1.09V      1.55V      52.68mV
378.8ns   172.2mV    1.314V     25.27mV
424.2ns   69.89mV    1.209V     24.55mV
772.7ns   36.15mV    138.6mV    23.91mV
1.5us     35.52mV    67.23mV    23.9mV
[Falling Waveform]
R_fixture = 70.0000
V_fixture = 1.8000
V_fixture_min = 1.6200
V_fixture_max = 1.8900
0s        1.8V       1.62V      1.89V
90.91ns   1.8V       1.621V     1.793V
151.5ns   1.727V     1.62V      1.409V
227.3ns   1.492V     1.613V     866.9mV
272.7ns   1.336V     1.595V     395.3mV
333.3ns   1.119V     1.548V     204.4mV
484.8ns   426.6mV    1.382V     167.5mV
590.9ns   290.4mV    1.252V     165mV
1.106us   241.8mV    553.7mV    164.3mV
2.02us    241.2mV    431.4mV    164.3mV
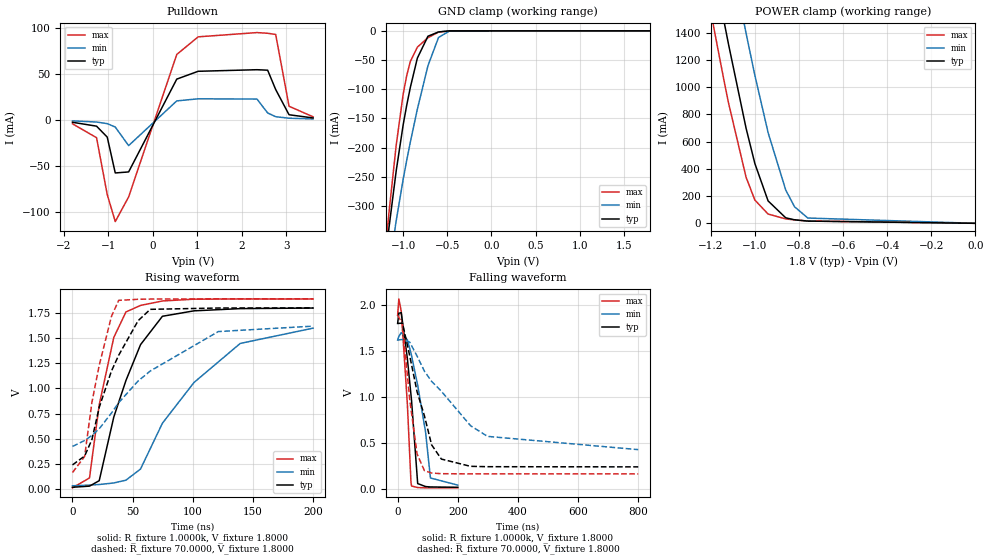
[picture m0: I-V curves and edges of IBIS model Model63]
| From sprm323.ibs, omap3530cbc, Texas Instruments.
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| Model based on original model for BQ0245S_7LM
|   Sub model BQ0245S_7LM_I2C_1
[model]   Model63
|[Input Load]
|[Output Drive] LOWC
|Voltage   1.8000V
|Mode   I/O_OPEN_DRAIN
Model_type   I/O_open_drain
Polarity   Non-Inverting
Enable   Active-Low
Vinl =   0.6615V
Vinh =   1.0530V
Vmeas =   0.9000V
Cref =  400pF
Rref =  70.0000
Vref =  1.800V
C_comp   27.0438pF   15.4231pF   39.2246pF
[Temperature Range]   25.0000   0.1250k   -40.0000
[Voltage Range]   1.8000V   1.6200V   1.8900V
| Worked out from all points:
|   slope of the pulldown table from 0 to 0.27 V, typ, clamps not added: 11 ohm
|   GND clamp passes 1 mA (typ) near -0.56 V on its own axis
|   POWER clamp passes 1 mA (typ) near -0.50 V on its own axis
|   rising waveform, R_fixture 1.0000k, V_fixture 1.8000: 20-80 % time 28.6ns typ, 59ns min, 17.4ns max; typ from 0.018 V to 1.8 V
|   rising waveform, R_fixture 70.0000, V_fixture 1.8000: 20-80 % time 27.8ns typ, 62.5ns min, 15.9ns max; typ from 0.24 V to 1.8 V
|   falling waveform, R_fixture 1.0000k, V_fixture 1.8000: 20-80 % time 27.9ns typ, 44ns min, 19.5ns max; typ from 1.8 V to 0.018 V
|   falling waveform, R_fixture 70.0000, V_fixture 1.8000: 20-80 % time 68.6ns typ, 176ns min, 36.1ns max; typ from 1.8 V to 0.24 V
[Pulldown]
-1.8V     -2.87mA    -1.375mA   -4.529mA
-1.26V    -7.104mA   -2.598mA   -19.64mA
-1.02V    -19.01mA   -4.336mA   -81.54mA
-840mV    -58.01mA   -8.07mA    -110.9mA
-540mV    -56.9mA    -28.27mA   -84.17mA
540mV     44.08mA    20.39mA    70.89mA
1.02V     52.6mA     22.66mA    90.08mA
2.34V     54.32mA    22.39mA    94.72mA
2.58V     53.78mA    7.279mA    93.97mA
2.76V     32.75mA    3.192mA    92.7mA
3.06V     5.313mA    1.539mA    14.56mA
3.6V      1.834mA    776uA      3.052mA
[GND_clamp]
-1.8V     -1.221A    -1.151A    -1.363A
-1.2V     -386.5mA   -449.7mA   -370.2mA
-1.16V    -335.5mA   -406.8mA   -309.4mA
-1.08V    -240.2mA   -325.8mA   -196.3mA
-1V       -160.3mA   -253.8mA   -107.7mA
-960mV    -127.1mA   -221.5mA   -76.33mA
-920mV    -97.28mA   -191.1mA   -52.71mA
-840mV    -46.78mA   -134.3mA   -27.94mA
-720mV    -9.253mA   -59.82mA   -11.79mA
-600mV    -1.888mA   -11.35mA   -2.27mA
-480mV    -137.6uA   -650.3uA   -84.11uA
1.8V      510.5nA    3.196uA    487.6nA
[POWER_clamp]
-1.8V     7.644A     8.363A     7.23A
-1.2V     2.004A     2.755A     1.56A
-1.18V    1.829A     2.578A     1.386A
-1.14V    1.486A     2.23A      1.05A
-1.12V    1.32A      2.059A     889mA
-1.04V    700.2mA    1.398A     339.6mA
-1V       439.3mA    1.088A     170.8mA
-940mV    164.6mA    666.7mA    68.12mA
-860mV    40.26mA    244.2mA    32.15mA
-820mV    25.73mA    121.5mA    25.04mA
-760mV    16.31mA    38.76mA    16.75mA
0V        510.5nA    462.5nA    537.3nA
[Ramp]
dV/dt_r   0.2729m/26.3267n  0.7493m/44.5155n  0.3413m/16.2150n
dV/dt_f   1.0690/28.0102n   0.9520/45.3069n   1.1265/19.3562n
R_load = 1.0000k
[Rising Waveform]
R_fixture = 1.0000k
V_fixture = 1.8000
V_fixture_min = 1.6200
V_fixture_max = 1.8900
0s        17.75mV    32.71mV    11.97mV
14.14ns   29.05mV    39.13mV    110.3mV
22.22ns   83.17mV    45.2mV     837.3mV
34.34ns   715.9mV    60.61mV    1.507V
44.44ns   1.079V     88.16mV    1.76V
56.57ns   1.435V     199.3mV    1.825V
74.75ns   1.717V     654.3mV    1.869V
101ns     1.771V     1.059V     1.887V
139.4ns   1.793V     1.447V     1.889V
200ns     1.799V     1.599V     1.889V
[Rising Waveform]
R_fixture = 70.0000
V_fixture = 1.8000
V_fixture_min = 1.6200
V_fixture_max = 1.8900
0s        239.9mV    423.4mV    164mV
10.1ns    327.9mV    482.5mV    324.3mV
16.16ns   491.9mV    533mV      862.7mV
22.22ns   811.6mV    598.8mV    1.229V
32.32ns   1.171V     754.2mV    1.714V
38.38ns   1.329V     858.3mV    1.875V
54.55ns   1.673V     1.074V     1.886V
64.65ns   1.786V     1.173V     1.888V
121.2ns   1.799V     1.565V     1.89V
200ns     1.8V       1.619V     1.89V
[Falling Waveform]
R_fixture = 1.0000k
V_fixture = 1.8000
V_fixture_min = 1.6200
V_fixture_max = 1.8900
0s        1.8V       1.619V     1.889V
4.04ns    1.91V      1.659V     2.067V
12.12ns   1.917V     1.7V       1.93V
32.32ns   1.419V     1.622V     926.8mV
44.44ns   1.023V     1.475V     69.81mV
46.46ns   952.7mV    1.446V     32.27mV
66.67ns   58.57mV    1.127V     14.89mV
92.93ns   25.84mV    618.6mV    12.6mV
109.1ns   21.79mV    119mV      12.24mV
200ns     18.11mV    41.71mV    11.98mV
[Falling Waveform]
R_fixture = 70.0000
V_fixture = 1.8000
V_fixture_min = 1.6200
V_fixture_max = 1.8900
0s        1.8V       1.62V      1.89V
16.16ns   1.803V     1.625V     1.794V
40.4ns    1.445V     1.595V     965.6mV
64.65ns   1.057V     1.445V     381.6mV
88.89ns   797.4mV    1.282V     199.6mV
113.1ns   478.9mV    1.169V     173.1mV
145.5ns   324.8mV    1.062V     165.9mV
242.4ns   246.1mV    687.8mV    164.1mV
299ns     241.9mV    571.6mV    164mV
800ns     240.1mV    427.5mV    164mV
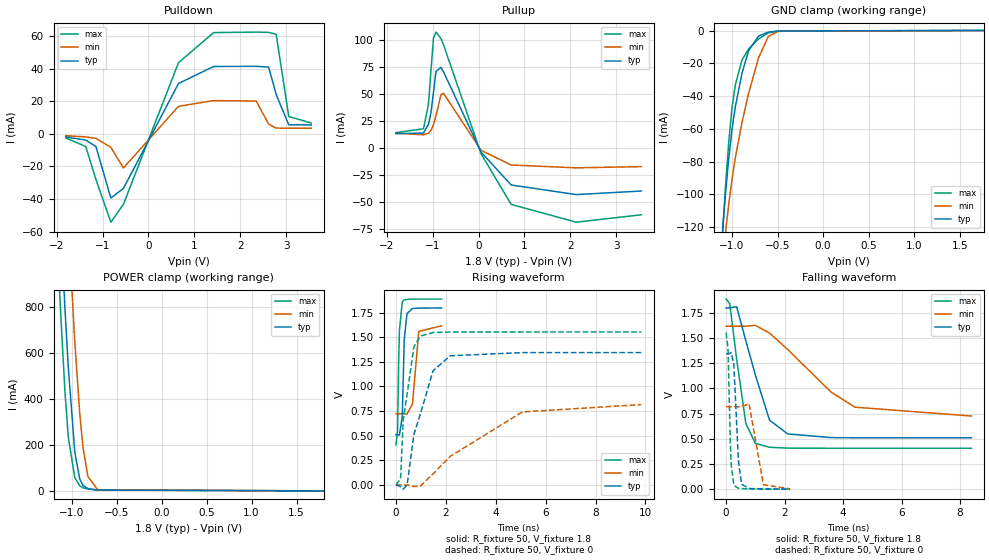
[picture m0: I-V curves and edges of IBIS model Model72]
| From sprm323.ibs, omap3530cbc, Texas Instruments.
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| Model based on original model for SDI2_7LM
|   Sub model SDI2_7LM_PD_ON_1P8
[model]   Model72
|[Input Load]   PD
|[Output Drive]
|Voltage   1.8V
|Mode   I/O
Model_type   I/O
Polarity   Non-Inverting
Enable   Active-Low
Vinl =  0.63
Vinh =  1.17
Cref =  15.0000pF
Rref =  100.0000M
Vref =  0V
Vmeas =  0.9
C_comp   0.898823p   0.7724811p   1.056895p
[Model Spec]
Vinl   0.63   0.567   0.6615
Vinh   1.17   1.053   1.2285
[Temperature Range]   25   125   -40
[Voltage Range]   1.8   1.62   1.89
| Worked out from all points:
|   slope of the pulldown table from 0 to 0.27 V, typ, clamps not added: 18.2 ohm
|   slope of the pullup table from 0 to 0.27 V, typ, clamps not added: 15.1 ohm
|   GND clamp passes 1 mA (typ) near -0.61 V on its own axis
|   POWER clamp passes 1 mA (typ) near -0.57 V on its own axis
|   rising waveform, R_fixture 50, V_fixture 1.8: 20-80 % time 83.5ps typ, 144ps min, 68.1ps max; typ from 0.51 V to 1.8 V
|   rising waveform, R_fixture 50, V_fixture 0: 20-80 % time 780ps typ, 2.5ns min, 384ps max; typ from 0 V to 1.34 V
|   falling waveform, R_fixture 50, V_fixture 1.8: 20-80 % time 759ps typ, 1.98ns min, 423ps max; typ from 1.8 V to 0.51 V
|   falling waveform, R_fixture 50, V_fixture 0: 20-80 % time 127ps typ, 249ps min, 81ps max; typ from 1.34 V to 0.001 V
[POWER_clamp]
-1.8V     7.03A      7.477A     6.772A
-1.182V   1.672A     2.34A      1.267A
-1.164V   1.518A     2.189A     1.114A
-1.127V   1.216A     1.889A     820.5mA
-1.073V   791.2mA    1.448A     431.2mA
-1.036V   538.2mA    1.164A     234.6mA
-963.6mV  168.9mA    647.7mA    57.34mA
-909.1mV  52.01mA    338.6mA    22.19mA
-872.7mV  24.21mA    189.8mA    13.44mA
-818.2mV  9.898mA    62.61mA    8.593mA
-709.1mV  3.884mA    5.003mA    3.858mA
1.8V      106uA      46.56uA    203.1uA
[Pulldown]
-1.8V     -1.896mA   -1.14mA    -2.549mA
-1.364V   -3.858mA   -1.868mA   -7.811mA
-1.145V   -7.758mA   -2.749mA   -27.91mA
-818.2mV  -39.37mA   -8.281mA   -54.21mA
-545.5mV  -33.49mA   -20.95mA   -43.25mA
654.5mV   30.89mA    16.9mA     43.68mA
1.418V    41.32mA    20.41mA    62.11mA
2.345V    41.43mA    20.12mA    62.44mA
2.618V    40.99mA    5.968mA    62.24mA
2.782V    24.07mA    3.525mA    61.09mA
3.055V    5.586mA    3.449mA    10.68mA
3.545V    5.467mA    3.446mA    6.63mA
[Pullup]
-1.8V     13mA       13.47mA    13.94mA
-1.2V     13.58mA    11.97mA    17.52mA
-1.091V   21.69mA    13.4mA     40.45mA
-1.036V   32.56mA    16.02mA    72.07mA
-981.8mV  51.55mA    21.35mA    101.5mA
-927.3mV  70.65mA    29.72mA    107.1mA
-818.2mV  74.4mA     49.19mA    101mA
-763.6mV  70.3mA     50.34mA    95.36mA
54.55mV   -4.057mA   -2.362mA   -5.698mA
709.1mV   -34.52mA   -16.04mA   -52.48mA
2.127V    -43.43mA   -18.65mA   -69mA
3.545V    -40.12mA   -17.52mA   -62.13mA
[GND_clamp]
-1.8V     -750.7mA   -623.4mA   -941.3mA
-1.109V   -125.8mA   -143.6mA   -129.9mA
-1.073V   -100.4mA   -124mA     -96.53mA
-1.036V   -78.35mA   -106.3mA   -68.3mA
-1V       -60.41mA   -90.83mA   -47.17mA
-963.6mV  -46.57mA   -77.68mA   -33.23mA
-890.9mV  -26.24mA   -56.24mA   -17.93mA
-818.2mV  -12.28mA   -38.4mA    -11.16mA
-709.1mV  -3.328mA   -16.68mA   -5.098mA
-600mV    -881.8uA   -3.435mA   -1.308mA
-490.9mV  -219.2uA   -344.7uA   -271.3uA
1.764V    105.9uA    46.69uA    203uA
[Ramp]
dV/dt_f  0.7830223/0.7661262n  0.5430895/2.014815n   0.9036707/0.4281507n
dV/dt_r  0.8333502/0.7812014n  0.5074355/2.533511n   0.9658344/0.3844317n
R_load = 50
[Rising Waveform]
R_fixture = 50
V_fixture = 1.8
V_fixture_min = 1.62
V_fixture_max = 1.89
0s        509.9mV    723.3mV    406.3mV
66ps      509.8mV    723.3mV    546.7mV
108ps     508.6mV    723.4mV    1.257V
142ps     507.1mV    723.5mV    1.574V
254ps     694.9mV    723.5mV    1.859V
334ps     1.479V     722.7mV    1.881V
442ps     1.74V      719.9mV    1.884V
662ps     1.792V     820.9mV    1.887V
916ps     1.796V     1.559V     1.888V
1.832ns   1.798V     1.616V     1.888V
[Rising Waveform]
R_fixture = 50
V_fixture = 0
V_fixture_min = 0
V_fixture_max = 0
0s        198.1nV    88.64nV    429.6nV
186ps     -15.34mV   13.59uV    62.83mV
292ps     -43.12mV   157uV      661.1mV
450ps     1.425mV    -38.68uV   923.7mV
720ps     512.8mV    -15.89mV   1.401V
978ps     720.5mV    -11.81mV   1.512V
1.488ns   1.159V     111.7mV    1.548V
2.178ns   1.312V     290.7mV    1.553V
5.064ns   1.344V     741.1mV    1.554V
9.834ns   1.344V     816.2mV    1.554V
[Falling Waveform]
R_fixture = 50
V_fixture = 1.8
V_fixture_min = 1.62
V_fixture_max = 1.89
0s        1.799V     1.619V     1.888V
126ps     1.8V       1.619V     1.844V
362ps     1.812V     1.619V     1.291V
678ps     1.472V     1.619V     651.7mV
1.002ns   1.135V     1.627V     454.9mV
1.486ns   685.7mV    1.551V     416.2mV
2.106ns   548.9mV    1.388V     408mV
3.594ns   512.3mV    962.9mV    406.3mV
4.41ns    510.5mV    814.2mV    406.3mV
8.392ns   509.9mV    726.5mV    406.3mV
[Falling Waveform]
R_fixture = 50
V_fixture = 0
V_fixture_min = 0
V_fixture_max = 0
0s        1.344V     819.5mV    1.554V
66ps      1.344V     819.6mV    1.404V
146ps     1.351V     819.2mV    466.8mV
176ps     1.356V     819mV      244.7mV
266ps     1.24V      818.6mV    36.92mV
424ps     278.7mV    818.2mV    8.406mV
532ps     48.85mV    819.8mV    5.94mV
786ps     6.638mV    849.4mV    2.115mV
1.278ns   2.126mV    44.1mV     800.2uV
2.192ns   820uV      3.248mV    115.4uV
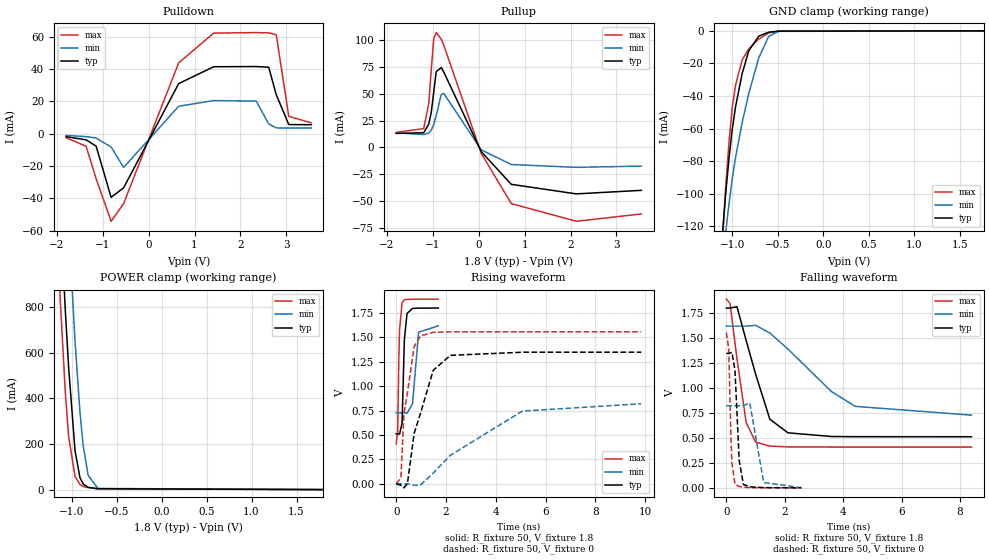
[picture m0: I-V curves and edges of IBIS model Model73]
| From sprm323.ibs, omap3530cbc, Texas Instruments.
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| Model based on original model for SDI2_7LM
|   Sub model SDI2_7LM_PU_ON_1P8
[model]   Model73
|[Input Load]   PU
|[Output Drive]
|Voltage   1.8V
|Mode   I/O
Model_type   I/O
Polarity   Non-Inverting
Enable   Active-Low
Vinl =  0.63
Vinh =  1.17
Cref =  15.0000pF
Rref =  100.0000M
Vref =  0V
Vmeas =  0.9
C_comp   0.898823p   0.7724811p   1.056895p
[Model Spec]
Vinl   0.63   0.567   0.6615
Vinh   1.17   1.053   1.2285
[Temperature Range]   25   125   -40
[Voltage Range]   1.8   1.62   1.89
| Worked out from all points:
|   slope of the pulldown table from 0 to 0.27 V, typ, clamps not added: 18.2 ohm
|   slope of the pullup table from 0 to 0.27 V, typ, clamps not added: 15.1 ohm
|   GND clamp passes 1 mA (typ) near -0.61 V on its own axis
|   POWER clamp passes 1 mA (typ) near -0.57 V on its own axis
|   rising waveform, R_fixture 50, V_fixture 1.8: 20-80 % time 82.3ps typ, 144ps min, 65.8ps max; typ from 0.513 V to 1.8 V
|   rising waveform, R_fixture 50, V_fixture 0: 20-80 % time 776ps typ, 2.5ns min, 382ps max; typ from 0.001 V to 1.35 V
|   falling waveform, R_fixture 50, V_fixture 1.8: 20-80 % time 759ps typ, 1.98ns min, 423ps max; typ from 1.8 V to 0.513 V
|   falling waveform, R_fixture 50, V_fixture 0: 20-80 % time 127ps typ, 251ps min, 82.3ps max; typ from 1.35 V to 0.002 V
[POWER_clamp]
-1.8V     7.03A      7.477A     6.772A
-1.182V   1.672A     2.34A      1.267A
-1.164V   1.518A     2.189A     1.114A
-1.127V   1.216A     1.889A     820.5mA
-1.073V   791.2mA    1.448A     431.2mA
-1.036V   538.2mA    1.164A     234.6mA
-963.6mV  169mA      647.7mA    57.34mA
-909.1mV  52.04mA    338.7mA    22.18mA
-872.7mV  24.24mA    189.9mA    13.43mA
-818.2mV  9.923mA    62.63mA    8.573mA
-709.1mV  3.896mA    5.034mA    3.819mA
1.8V      4.83nA     3.513nA    7.993nA
[Pulldown]
-1.8V     -1.896mA   -1.14mA    -2.549mA
-1.364V   -3.858mA   -1.868mA   -7.811mA
-1.145V   -7.758mA   -2.749mA   -27.9mA
-818.2mV  -39.37mA   -8.281mA   -54.21mA
-545.5mV  -33.5mA    -20.95mA   -43.25mA
654.5mV   30.89mA    16.9mA     43.69mA
1.418V    41.32mA    20.41mA    62.11mA
2.345V    41.43mA    20.12mA    62.44mA
2.618V    40.99mA    5.968mA    62.24mA
2.782V    24.07mA    3.525mA    61.09mA
3.055V    5.586mA    3.449mA    10.68mA
3.545V    5.467mA    3.446mA    6.63mA
[Pullup]
-1.8V     13mA       13.47mA    13.94mA
-1.2V     13.58mA    11.97mA    17.52mA
-1.091V   21.69mA    13.4mA     40.45mA
-1.036V   32.56mA    16.02mA    72.07mA
-981.8mV  51.55mA    21.35mA    101.5mA
-927.3mV  70.65mA    29.73mA    107.1mA
-818.2mV  74.4mA     49.19mA    101mA
-763.6mV  70.3mA     50.34mA    95.36mA
54.55mV   -4.056mA   -2.362mA   -5.695mA
709.1mV   -34.52mA   -16.04mA   -52.48mA
2.127V    -43.43mA   -18.65mA   -69.01mA
3.545V    -40.12mA   -17.52mA   -62.13mA
[GND_clamp]
-1.8V     -750.7mA   -623.4mA   -941.3mA
-1.109V   -125.8mA   -143.6mA   -129.9mA
-1.073V   -100.4mA   -123.9mA   -96.49mA
-1.036V   -78.32mA   -106.3mA   -68.25mA
-1V       -60.38mA   -90.82mA   -47.12mA
-963.6mV  -46.53mA   -77.67mA   -33.17mA
-890.9mV  -26.18mA   -56.23mA   -17.84mA
-818.2mV  -12.21mA   -38.39mA   -11.07mA
-709.1mV  -3.262mA   -16.66mA   -5.009mA
-600mV    -830.6uA   -3.399mA   -1.237mA
-490.9mV  -189.8uA   -313.9uA   -230uA
1.764V    -5.54uA    14.06uA    -26.2uA
[Ramp]
dV/dt_f  0.7827806/0.7668391n  0.5423742/2.015367n   0.90496/0.4288422n
dV/dt_r  0.8328674/0.7774813n  0.5085602/2.531051n   0.9647627/0.3821132n
R_load = 50
[Rising Waveform]
R_fixture = 50
V_fixture = 1.8
V_fixture_min = 1.62
V_fixture_max = 1.89
0s        513.1mV    725.9mV    409.7mV
60ps      512.9mV    725.9mV    534.4mV
108ps     511.6mV    726.1mV    1.325V
136ps     510.3mV    726.1mV    1.579V
236ps     620.6mV    726.2mV    1.854V
328ps     1.476V     725.4mV    1.884V
436ps     1.744V     722.6mV    1.887V
656ps     1.795V     820.4mV    1.889V
900ps     1.798V     1.552V     1.889V
1.69ns    1.799V     1.617V     1.89V
[Rising Waveform]
R_fixture = 50
V_fixture = 0
V_fixture_min = 0
V_fixture_max = 0
0s        1.238mV    776.6uV    1.504mV
188ps     -13.69mV   789.3uV    60.36mV
310ps     -40.4mV    952.1uV    716mV
450ps     3.061mV    777.9uV    929.2mV
720ps     515.3mV    -14.63mV   1.403V
978ps     724.1mV    -10.14mV   1.515V
1.488ns   1.162V     111.8mV    1.55V
2.178ns   1.315V     293.1mV    1.556V
5.064ns   1.347V     744.6mV    1.556V
9.848ns   1.347V     819.9mV    1.556V
[Falling Waveform]
R_fixture = 50
V_fixture = 1.8
V_fixture_min = 1.62
V_fixture_max = 1.89
0s        1.8V       1.62V      1.89V
126ps     1.801V     1.62V      1.847V
364ps     1.814V     1.62V      1.294V
680ps     1.475V     1.62V      654.1mV
1.004ns   1.138V     1.628V     458.8mV
1.49ns    687.9mV    1.551V     419.6mV
2.11ns    552.2mV    1.39V      411.3mV
3.598ns   515.4mV    965mV      409.7mV
4.414ns   513.6mV    816.8mV    409.7mV
8.392ns   513.1mV    729.2mV    409.7mV
[Falling Waveform]
R_fixture = 50
V_fixture = 0
V_fixture_min = 0
V_fixture_max = 0
0s        1.347V     823.1mV    1.556V
82ps      1.347V     823.2mV    1.395V
156ps     1.353V     822.8mV    521.2mV
192ps     1.359V     822.6mV    248.2mV
296ps     1.178V     822.2mV    38.06mV
440ps     277.8mV    821.9mV    14.83mV
584ps     35.5mV     825.6mV    8.115mV
802ps     11.87mV    851.4mV    3.941mV
1.28ns    3.955mV    54.06mV    2.377mV
2.566ns   1.79mV     4.027mV    1.555mV
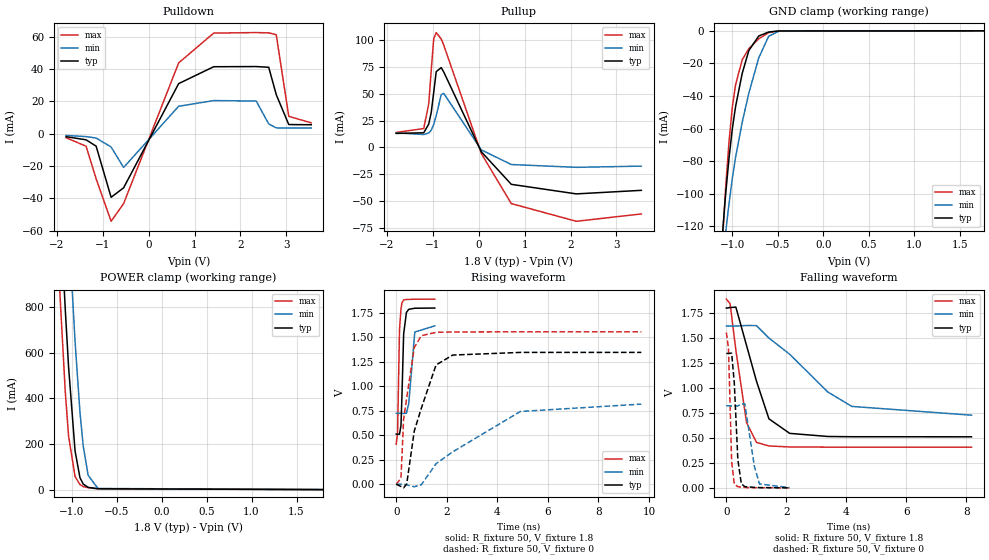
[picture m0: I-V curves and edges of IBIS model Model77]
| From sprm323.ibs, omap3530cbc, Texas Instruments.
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| Model based on original model for BQ0234CS_7LM
|   Sub model 0234CS_PD_PU_OFF_1P8
[model]   Model77
|[Input Load]   PI
|[Output Drive]
|Voltage   1.8V
|Mode   I/O
Model_type   I/O
Polarity   Non-Inverting
Enable   Active-Low
Vinl =  0.63
Vinh =  1.17
Cref =  15.0000pF
Rref =  100.0000M
Vref =  0V
Vmeas =  0.9
C_comp   0.8818576p   0.7571797p   1.039848p
[Model Spec]
Vinl   0.63   0.567   0.6615
Vinh   1.17   1.053   1.2285
[Temperature Range]   25   125   -40
[Voltage Range]   1.8   1.62   1.89
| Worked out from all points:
|   slope of the pulldown table from 0 to 0.27 V, typ, clamps not added: 18.2 ohm
|   slope of the pullup table from 0 to 0.27 V, typ, clamps not added: 15.1 ohm
|   GND clamp passes 1 mA (typ) near -0.62 V on its own axis
|   POWER clamp passes 1 mA (typ) near -0.57 V on its own axis
|   rising waveform, R_fixture 50, V_fixture 1.8: 20-80 % time 81.2ps typ, 139ps min, 65.2ps max; typ from 0.511 V to 1.8 V
|   rising waveform, R_fixture 50, V_fixture 0: 20-80 % time 780ps typ, 2.51ns min, 383ps max; typ from 0 V to 1.35 V
|   falling waveform, R_fixture 50, V_fixture 1.8: 20-80 % time 757ps typ, 1.98ns min, 422ps max; typ from 1.8 V to 0.511 V
|   falling waveform, R_fixture 50, V_fixture 0: 20-80 % time 127ps typ, 249ps min, 81ps max; typ from 1.35 V to 0.001 V
[POWER_clamp]
-1.8V     7.03A      7.477A     6.772A
-1.182V   1.672A     2.34A      1.267A
-1.164V   1.518A     2.189A     1.114A
-1.127V   1.216A     1.889A     820.4mA
-1.073V   791.2mA    1.448A     431.2mA
-1.036V   538.2mA    1.164A     234.5mA
-963.6mV  168.9mA    647.7mA    57.19mA
-909.1mV  51.95mA    338.6mA    22.02mA
-872.7mV  24.13mA    189.8mA    13.26mA
-818.2mV  9.807mA    62.59mA    8.409mA
-709.1mV  3.786mA    4.97mA     3.667mA
1.8V      5.391nA    3.441nA    8.971nA
[Pulldown]
-1.8V     -1.896mA   -1.14mA    -2.549mA
-1.364V   -3.858mA   -1.868mA   -7.811mA
-1.145V   -7.758mA   -2.749mA   -27.9mA
-818.2mV  -39.37mA   -8.28mA    -54.21mA
-545.5mV  -33.5mA    -20.95mA   -43.25mA
654.5mV   30.89mA    16.9mA     43.69mA
1.418V    41.32mA    20.41mA    62.11mA
2.345V    41.43mA    20.12mA    62.44mA
2.618V    40.99mA    5.968mA    62.24mA
2.782V    24.07mA    3.525mA    61.09mA
3.055V    5.586mA    3.449mA    10.68mA
3.545V    5.467mA    3.446mA    6.63mA
[Pullup]
-1.8V     13mA       13.47mA    13.94mA
-1.2V     13.58mA    11.97mA    17.52mA
-1.091V   21.69mA    13.4mA     40.44mA
-1.036V   32.56mA    16.02mA    72.05mA
-981.8mV  51.54mA    21.35mA    101.5mA
-927.3mV  70.65mA    29.72mA    107.1mA
-818.2mV  74.4mA     49.19mA    101mA
-763.6mV  70.3mA     50.34mA    95.36mA
54.55mV   -4.056mA   -2.362mA   -5.695mA
709.1mV   -34.52mA   -16.04mA   -52.48mA
2.127V    -43.43mA   -18.65mA   -69.01mA
3.545V    -40.12mA   -17.52mA   -62.13mA
[GND_clamp]
-1.8V     -750.6mA   -623.3mA   -941.3mA
-1.109V   -125.7mA   -143.5mA   -129.8mA
-1.073V   -100.3mA   -123.9mA   -96.46mA
-1.036V   -78.28mA   -106.2mA   -68.22mA
-1V       -60.33mA   -90.75mA   -47.08mA
-963.6mV  -46.48mA   -77.6mA    -33.12mA
-890.9mV  -26.13mA   -56.16mA   -17.76mA
-818.2mV  -12.14mA   -38.32mA   -10.94mA
-709.1mV  -3.177mA   -16.6mA    -4.873mA
-600mV    -740.6uA   -3.353mA   -1.096mA
-490.9mV  -93.6uA    -272.6uA   -80.84uA
1.764V    4.431nA    31.14nA    4.817nA
[Ramp]
dV/dt_f  0.7815847/0.762961n   0.5423991/2.007497n   0.9022311/0.426199n
dV/dt_r  0.8347437/0.7806594n  0.5087701/2.538366n   0.9675667/0.3832303n
R_load = 50
[Rising Waveform]
R_fixture = 50
V_fixture = 1.8
V_fixture_min = 1.62
V_fixture_max = 1.89
0s        511.5mV    724.7mV    407.9mV
54ps      511.4mV    724.7mV    522.6mV
130ps     510.8mV    725mV      1.577V
188ps     596.4mV    725.3mV    1.788V
228ps     908.7mV    724.8mV    1.852V
294ps     1.534V     722.1mV    1.881V
404ps     1.754V     725mV      1.887V
496ps     1.786V     820.7mV    1.887V
734ps     1.797V     1.554V     1.889V
1.526ns   1.799V     1.617V     1.89V
[Rising Waveform]
R_fixture = 50
V_fixture = 0
V_fixture_min = 0
V_fixture_max = 0
0s        196.5nV    87.63nV    427nV
188ps     -22.48mV   203.7uV    61.59mV
292ps     -36.9mV    277.1uV    660.2mV
416ps     3.442mV    -5.764mV   881.9mV
714ps     542.8mV    -25.79mV   1.396V
996ps     777.9mV    -4.166mV   1.517V
1.576ns   1.218V     209.7mV    1.551V
2.236ns   1.319V     331.1mV    1.555V
4.91ns    1.346V     742.9mV    1.556V
9.696ns   1.346V     818.1mV    1.556V
[Falling Waveform]
R_fixture = 50
V_fixture = 1.8
V_fixture_min = 1.62
V_fixture_max = 1.89
0s        1.8V       1.62V      1.89V
126ps     1.806V     1.62V      1.844V
318ps     1.81V      1.62V      1.379V
674ps     1.426V     1.626V     654.6mV
1.006ns   1.068V     1.625V     455.6mV
1.422ns   691.1mV    1.5V       419.9mV
2.114ns   545.8mV    1.338V     409.5mV
3.384ns   514.6mV    960.7mV    408mV
4.186ns   512.2mV    815.7mV    407.9mV
8.18ns    511.5mV    727.9mV    407.9mV
[Falling Waveform]
R_fixture = 50
V_fixture = 0
V_fixture_min = 0
V_fixture_max = 0
0s        1.346V     821.4mV    1.556V
72ps      1.346V     821.4mV    1.398V
178ps     1.349V     820.6mV    260.4mV
266ps     1.048V     820mV      36.76mV
384ps     283.8mV    820.8mV    11.83mV
500ps     41.06mV    838.9mV    7.741mV
616ps     12.49mV    841.9mV    3.675mV
936ps     4.917mV    214.8mV    1.607mV
1.108ns   2.841mV    39.08mV    1.138mV
2.106ns   866.5uV    3.246mV    147.6uV
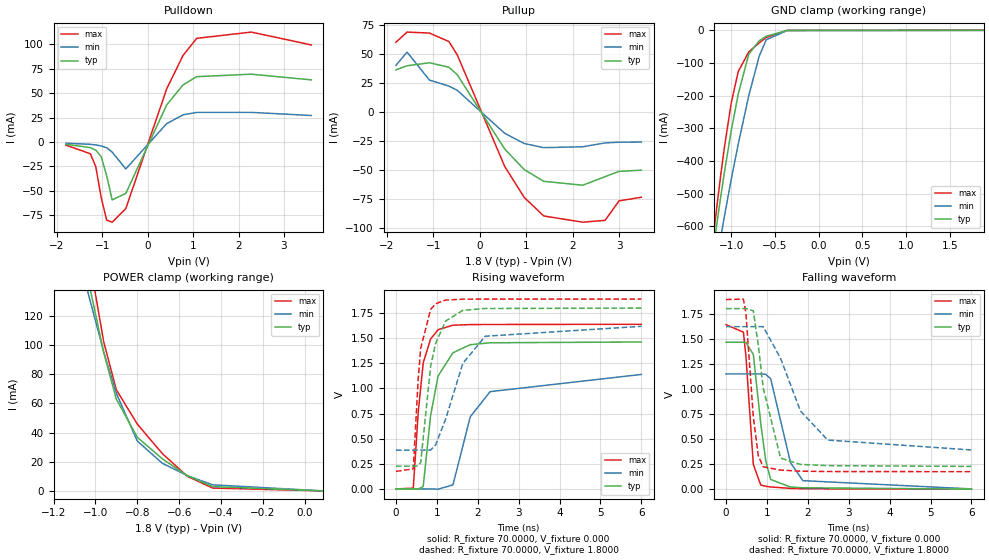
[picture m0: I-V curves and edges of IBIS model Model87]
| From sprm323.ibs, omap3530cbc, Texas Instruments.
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| Model based on original model for BQ0247S_7LM
|   Sub model BQ0247S_7LM_18
[model]   Model87
|[Input Load]   PI
|[Output Drive]
|Voltage   1.8000V
|Mode   I/O
Model_type   I/O
Polarity   Non-Inverting
Enable   Active-Low
Vinl =   0.6615V
Vinh =   1.0530V
Vmeas =   0.9000V
Cref =  15.0000pF
Rref =  70.0000
Vref =  0.000V
C_comp   14.0442pF   14.1784pF   14.5599pF
[Temperature Range]   25.0000   0.1250k   -40.0000
[Voltage Range]   1.8000V   1.6200V   1.8900V
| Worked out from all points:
|   slope of the pulldown table from 0 to 0.27 V, typ, clamps not added: 10.4 ohm
|   slope of the pullup table from 0 to 0.27 V, typ, clamps not added: 15.9 ohm
|   GND clamp passes 1 mA (typ) near -0.41 V on its own axis
|   POWER clamp passes 1 mA (typ) near -0.37 V on its own axis
|   rising waveform, R_fixture 70.0000, V_fixture 0.000: 20-80 % time 334ps typ, 601ps min, 210ps max; typ from 0 V to 1.46 V
|   rising waveform, R_fixture 70.0000, V_fixture 1.8000: 20-80 % time 304ps typ, 655ps min, 193ps max; typ from 0.226 V to 1.8 V
|   falling waveform, R_fixture 70.0000, V_fixture 0.000: 20-80 % time 250ps typ, 405ps min, 162ps max; typ from 1.47 V to 0.001 V
|   falling waveform, R_fixture 70.0000, V_fixture 1.8000: 20-80 % time 356ps typ, 788ps min, 201ps max; typ from 1.8 V to 0.227 V
[Pulldown]
-1.8V     -2.315mA   -1.247mA   -3.18mA
-1.26V    -5.735mA   -2.395mA   -12.01mA
-1.14V    -8.407mA   -3.014mA   -25.29mA
-1.02V    -15.01mA   -4.055mA   -57.13mA
-900mV    -34.53mA   -5.974mA   -79.95mA
-780mV    -59.24mA   -10.29mA   -82.03mA
-480mV    -52.65mA   -27.56mA   -68.16mA
420mV     37.97mA    18.77mA    54.35mA
780mV     58.41mA    27.78mA    88.55mA
1.08V     66.8mA     30.24mA    106mA
2.28V     69.36mA    30.28mA    112.4mA
3.6V      63.53mA    27.1mA     99.3mA
[Pullup]
-1.8V     36.49mA    40.41mA    60.33mA
-1.56V    40.02mA    51.79mA    69.09mA
-1.08V    42.61mA    27.69mA    68.26mA
-660mV    38.74mA    22.49mA    60.94mA
-480mV    32.28mA    18.83mA    49.4mA
540mV     -31.82mA   -18.28mA   -46.84mA
960mV     -49.54mA   -27.06mA   -73.55mA
1.38V     -59.71mA   -30.65mA   -89.61mA
2.22V     -63.07mA   -29.86mA   -94.98mA
2.7V      -55.69mA   -26.56mA   -93.38mA
3V        -51.12mA   -25.94mA   -76.6mA
3.48V     -50.1mA    -25.83mA   -73.43mA
[GND_clamp]
-1.8V     -1.9A      -1.807A    -2.065A
-1.2V     -659.6mA   -761.2mA   -618.3mA
-1.16V    -582.8mA   -696.2mA   -528.9mA
-1.12V    -508.3mA   -632.8mA   -442.5mA
-1.08V    -436.9mA   -571.4mA   -360.9mA
-1V       -307.1mA   -455.6mA   -221.8mA
-920mV    -194.8mA   -348.2mA   -126.3mA
-800mV    -73.11mA   -200.3mA   -66.07mA
-680mV    -32mA      -78.98mA   -38.37mA
-600mV    -18.2mA    -28.89mA   -21.88mA
-360mV    -271.5uA   -656uA     -163.3uA
1.89V     0A         0A         0A
[POWER_clamp]
-1.8V     791.2mA    693.9mA    1.001A
-1.1V     193mA      173.2mA    224.6mA
-1.08V    177.9mA    161.4mA    205.4mA
-1.06V    163.1mA    149.8mA    186.6mA
-1.04V    148.6mA    138.4mA    168.2mA
-960mV    94.77mA    95.29mA    102.1mA
-900mV    62.97mA    66.99mA    69.4mA
-800mV    36.81mA    34.25mA    45.87mA
-680mV    21.99mA    18.93mA    25.56mA
-560mV    10.37mA    10.43mA    9.987mA
-440mV    2.949mA    4.192mA    1.986mA
90mV      0A         0A         0A
[Ramp]
dV/dt_r   0.8769/0.3308n   0.6835/0.5955n   0.9829/0.2079n
dV/dt_f   0.9436/0.3524n   0.7373/0.7798n   1.0290/0.1986n
R_load = 70.0000
[Rising Waveform]
R_fixture = 70.0000
V_fixture = 0.000
V_fixture_min = 0.000
V_fixture_max = 0.000
0s        104.3uV    181.9uV    83.86uV
424.2ps   33.36uV    171.6uV    7.347mV
545.5ps   -502.8uV   175.4uV    764.4mV
666.7ps   22.58mV    116.9uV    1.253V
848.5ps   732.4mV    -141.5uV   1.493V
1.03ns    1.123V     -2.496mV   1.584V
1.394ns   1.355V     39.92mV    1.629V
1.818ns   1.435V     717.8mV    1.635V
2.303ns   1.454V     967.9mV    1.636V
6ns       1.462V     1.139V     1.638V
[Rising Waveform]
R_fixture = 70.0000
V_fixture = 1.8000
V_fixture_min = 1.6200
V_fixture_max = 1.8900
0s        226.3mV    386mV      174.4mV
424.2ps   226.4mV    386.1mV    199.8mV
545.5ps   228.8mV    386.2mV    1.1V
606.1ps   264.4mV    386.2mV    1.4V
848.5ps   1.22V      387.5mV    1.786V
969.7ps   1.447V     437.1mV    1.842V
1.212ns   1.669V     690.9mV    1.879V
1.636ns   1.777V     1.249V     1.888V
2.182ns   1.795V     1.519V     1.889V
6ns       1.799V     1.618V     1.889V
[Falling Waveform]
R_fixture = 70.0000
V_fixture = 0.000
V_fixture_min = 0.000
V_fixture_max = 0.000
0s        1.465V     1.149V     1.64V
424.2ps   1.465V     1.149V     1.565V
484.8ps   1.465V     1.149V     1.333V
666.7ps   1.343V     1.149V     246.8mV
848.5ps   654.3mV    1.149V     41.61mV
969.7ps   284.8mV    1.145V     29.38mV
1.091ns   97.02mV    1.101V     22.62mV
1.576ns   21.95mV    264.1mV    8.157mV
1.879ns   14.57mV    85.3mV     4.41mV
6ns       851.5uV    3.109mV    524.6uV
[Falling Waveform]
R_fixture = 70.0000
V_fixture = 1.8000
V_fixture_min = 1.6200
V_fixture_max = 1.8900
0s        1.8V       1.62V      1.89V
424.2ps   1.8V       1.62V      1.895V
484.8ps   1.8V       1.62V      1.758V
666.7ps   1.778V     1.62V      723.9mV
787.9ps   1.438V     1.62V      332mV
909.1ps   1.01V      1.62V      223.3mV
1.333ns   310.1mV    1.304V     190.3mV
1.818ns   247.1mV    780.4mV    180.1mV
2.485ns   234.9mV    490mV      176.3mV
6ns       227.2mV    391mV      174.9mV
